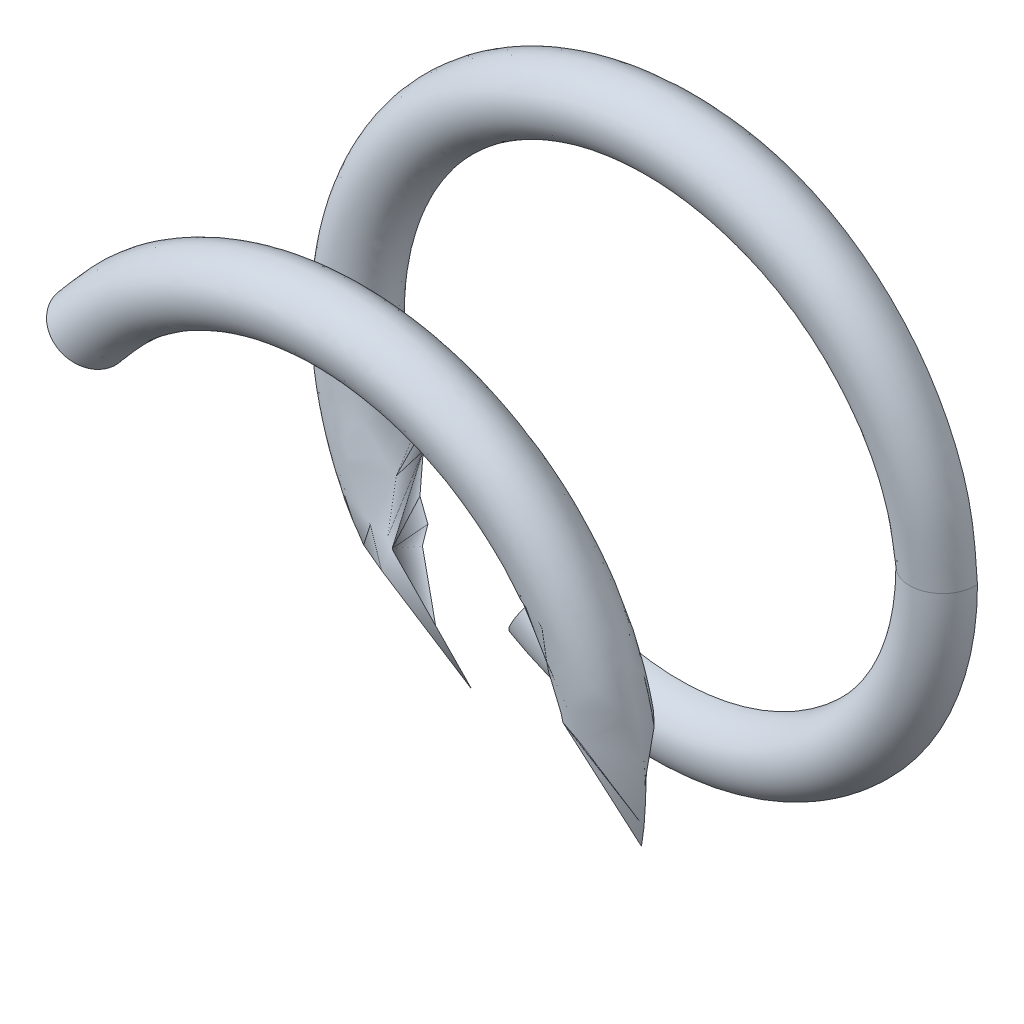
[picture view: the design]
ISO-10303-21;
HEADER;
FILE_DESCRIPTION(('STEP AP214'),'2;1');
FILE_NAME('part.step','',(''),(''),'','','');
FILE_SCHEMA(('AUTOMOTIVE_DESIGN { 1 0 10303 214 1 1 1 1 }'));
ENDSEC;
DATA;
#1=APPLICATION_CONTEXT('core data for automotive mechanical design processes');
#2=APPLICATION_PROTOCOL_DEFINITION('international standard','automotive_design',2000,#1);
#3=PRODUCT_CONTEXT('',#1,'mechanical');
#4=PRODUCT('Part','Part','',(#3));
#5=PRODUCT_RELATED_PRODUCT_CATEGORY('part','',(#4));
#6=PRODUCT_DEFINITION_FORMATION('','',#4);
#7=PRODUCT_DEFINITION_CONTEXT('part definition',#1,'design');
#8=PRODUCT_DEFINITION('design','',#6,#7);
#9=PRODUCT_DEFINITION_SHAPE('','',#8);
#10=(LENGTH_UNIT() NAMED_UNIT(*) SI_UNIT(.MILLI.,.METRE.));
#11=(NAMED_UNIT(*) PLANE_ANGLE_UNIT() SI_UNIT($,.RADIAN.));
#12=(NAMED_UNIT(*) SI_UNIT($,.STERADIAN.) SOLID_ANGLE_UNIT());
#13=UNCERTAINTY_MEASURE_WITH_UNIT(LENGTH_MEASURE(1.E-05),#10,'distance_accuracy_value','');
#14=(GEOMETRIC_REPRESENTATION_CONTEXT(3) GLOBAL_UNCERTAINTY_ASSIGNED_CONTEXT((#13)) GLOBAL_UNIT_ASSIGNED_CONTEXT((#10,
#11,#12)) REPRESENTATION_CONTEXT('',''));
#15=CARTESIAN_POINT('',(0.,0.,0.));
#16=DIRECTION('',(0.,0.,1.));
#17=DIRECTION('',(1.,0.,0.));
#18=AXIS2_PLACEMENT_3D('',#15,#16,#17);
#19=CARTESIAN_POINT('',(12.,0.,1.5));
#20=CARTESIAN_POINT('',(11.9418927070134,0.888508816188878,1.55892430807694));
#21=CARTESIAN_POINT('',(11.8254807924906,2.66854376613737,1.67697302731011));
#22=CARTESIAN_POINT('',(10.9146193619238,5.20828516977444,1.85413695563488));
#23=CARTESIAN_POINT('',(9.50351753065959,7.49108137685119,2.0312750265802));
#24=CARTESIAN_POINT('',(7.612969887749,9.4020238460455,2.20834408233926));
#25=CARTESIAN_POINT('',(5.35173785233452,10.8517466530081,2.3853875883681));
#26=CARTESIAN_POINT('',(2.8241644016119,11.7636999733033,2.56252409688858));
#27=CARTESIAN_POINT('',(0.158422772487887,12.0990888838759,2.73957486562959));
#28=CARTESIAN_POINT('',(-2.51533122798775,11.8334460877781,2.91666327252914));
#29=CARTESIAN_POINT('',(-5.0656074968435,10.9883084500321,3.09375974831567));
#30=CARTESIAN_POINT('',(-7.36509357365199,9.59829820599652,3.27081824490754));
#31=CARTESIAN_POINT('',(-9.30210830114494,7.73654640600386,3.44793628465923));
#32=CARTESIAN_POINT('',(-10.7805494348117,5.49293821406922,3.62497834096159));
#33=CARTESIAN_POINT('',(-11.7258602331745,2.97799692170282,3.8021033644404));
#34=CARTESIAN_POINT('',(-12.0958270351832,0.31675811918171,3.97915157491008));
#35=CARTESIAN_POINT('',(-11.8653071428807,-2.3601936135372,4.15625805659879));
#36=CARTESIAN_POINT('',(-11.0539405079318,-4.92146957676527,4.33333370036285));
#37=CARTESIAN_POINT('',(-9.69359276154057,-7.2386166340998,4.51040787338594));
#38=CARTESIAN_POINT('',(-7.85793807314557,-9.20036793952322,4.68751556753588));
#39=CARTESIAN_POINT('',(-5.63336414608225,-10.7073455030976,4.86456316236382));
#40=CARTESIAN_POINT('',(-3.13134399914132,-11.6862177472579,5.04168825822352));
#41=CARTESIAN_POINT('',(-0.475027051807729,-12.0903507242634,5.21873018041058));
#42=CARTESIAN_POINT('',(2.2046758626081,-11.8952806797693,5.39584853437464));
#43=CARTESIAN_POINT('',(4.77640624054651,-11.1174868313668,5.57290865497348));
#44=CARTESIAN_POINT('',(7.11097475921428,-9.7873304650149,5.74999960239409));
#45=CARTESIAN_POINT('',(9.09701650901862,-7.97795538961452,5.92709199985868));
#46=CARTESIAN_POINT('',(10.6323245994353,-5.77282598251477,6.10415094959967));
#47=CARTESIAN_POINT('',(11.6446337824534,-3.28417762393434,6.28127007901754));
#48=CARTESIAN_POINT('',(12.0827018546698,-0.633204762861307,6.45831173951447));
#49=CARTESIAN_POINT('',(11.9233675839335,2.04880154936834,6.63543656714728));
#50=CARTESIAN_POINT('',(11.1789246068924,4.63044315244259,6.81248492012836));
#51=CARTESIAN_POINT('',(9.87952006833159,6.98219921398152,6.98959141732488));
#52=CARTESIAN_POINT('',(8.09653525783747,8.9920289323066,7.16666702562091));
#53=CARTESIAN_POINT('',(5.91132700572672,10.5555447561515,7.34374120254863));
#54=CARTESIAN_POINT('',(3.43645684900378,11.6010656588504,7.52084890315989));
#55=CARTESIAN_POINT('',(0.791264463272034,12.0729424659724,7.69789649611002));
#56=CARTESIAN_POINT('',(-1.89258789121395,11.9495234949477,7.87502159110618));
#57=CARTESIAN_POINT('',(-4.48362986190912,11.2382958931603,8.05206351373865));
#58=CARTESIAN_POINT('',(-6.85231815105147,9.97015717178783,8.22918186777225));
#59=CARTESIAN_POINT('',(-8.88535349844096,8.21359015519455,8.40624198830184));
#60=CARTESIAN_POINT('',(-10.4770646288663,6.04887728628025,8.58333293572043));
#61=CARTESIAN_POINT('',(-11.5554649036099,3.5881349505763,8.76042533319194));
#62=CARTESIAN_POINT('',(-12.0611317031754,0.949182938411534,8.93748428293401));
#63=CARTESIAN_POINT('',(-11.9736976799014,-1.73605370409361,9.11460341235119));
#64=CARTESIAN_POINT('',(-11.2956449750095,-4.33601625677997,9.29164507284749));
#65=CARTESIAN_POINT('',(-10.0592156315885,-6.72134385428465,9.46876990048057));
#66=CARTESIAN_POINT('',(-8.32908489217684,-8.77699857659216,9.64581825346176));
#67=CARTESIAN_POINT('',(-6.18547441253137,-10.3969192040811,9.8229247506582));
#68=CARTESIAN_POINT('',(-3.7391653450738,-11.5077847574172,10.0000003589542));
#69=CARTESIAN_POINT('',(-1.10693909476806,-12.0473232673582,10.177074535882));
#70=CARTESIAN_POINT('',(1.57921895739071,-11.9958337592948,10.3541822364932));
#71=CARTESIAN_POINT('',(4.18765203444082,-11.3510180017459,10.5312298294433));
#72=CARTESIAN_POINT('',(6.5892741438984,-10.1466480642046,10.7083549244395));
#73=CARTESIAN_POINT('',(8.66702643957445,-8.44303760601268,10.885396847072));
#74=CARTESIAN_POINT('',(10.3151323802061,-6.3211029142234,11.0625152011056));
#75=CARTESIAN_POINT('',(11.4579424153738,-3.88948912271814,11.2395753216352));
#76=CARTESIAN_POINT('',(12.0315748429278,-1.26451827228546,11.4166662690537));
#77=CARTESIAN_POINT('',(12.0158684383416,1.42210661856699,11.5937586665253));
#78=CARTESIAN_POINT('',(11.4044595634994,4.03858245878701,11.7708176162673));
#79=CARTESIAN_POINT('',(10.2324004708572,6.45610557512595,11.9479367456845));
#80=CARTESIAN_POINT('',(8.55546846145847,8.55550067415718,12.1249784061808));
#81=CARTESIAN_POINT('',(6.45573391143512,10.2317047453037,12.3021032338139));
#82=CARTESIAN_POINT('',(4.03907073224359,11.4059312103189,12.4791515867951));
#83=CARTESIAN_POINT('',(1.42190403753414,12.0139174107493,12.6562580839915));
#84=CARTESIAN_POINT('',(-1.26474022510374,12.0337400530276,12.8333336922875));
#85=CARTESIAN_POINT('',(-3.88884864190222,11.4560101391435,13.0104078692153));
#86=CARTESIAN_POINT('',(-6.32183345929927,10.3164132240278,13.1875155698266));
#87=CARTESIAN_POINT('',(-8.44248545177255,8.66639940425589,13.3645631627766));
#88=CARTESIAN_POINT('',(-10.1466150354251,6.58932500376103,13.5416882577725));
#89=CARTESIAN_POINT('',(-11.3518154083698,4.18790141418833,13.7187301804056));
#90=CARTESIAN_POINT('',(-11.9943665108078,1.57907253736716,13.8958485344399));
#91=CARTESIAN_POINT('',(-12.0493489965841,-1.10713991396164,14.0729086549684));
#92=CARTESIAN_POINT('',(-11.5057164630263,-3.73848743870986,14.24999960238));
#93=CARTESIAN_POINT('',(-10.3986191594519,-6.18645303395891,14.4270919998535));
#94=CARTESIAN_POINT('',(-8.77585275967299,-8.32804026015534,14.6041509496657));
#95=CARTESIAN_POINT('',(-6.72182826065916,-10.0598381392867,14.7812700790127));
#96=CARTESIAN_POINT('',(-4.33597372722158,-11.2956612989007,14.9583117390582));
#97=CARTESIAN_POINT('',(-1.73599715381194,-11.9729109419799,15.1354365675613));
#98=CARTESIAN_POINT('',(0.949335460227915,-12.0626747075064,15.3124849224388));
#99=CARTESIAN_POINT('',(3.58752645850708,-11.5536001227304,15.4895914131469));
#100=CARTESIAN_POINT('',(6.04996074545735,-10.4789525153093,15.6666670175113));
#101=CARTESIAN_POINT('',(8.21221908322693,-8.88384871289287,15.8437412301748));
#102=CARTESIAN_POINT('',(9.9713452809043,-6.85319072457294,16.0208489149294));
#103=CARTESIAN_POINT('',(11.2375374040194,-4.48328224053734,16.1978963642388));
#104=CARTESIAN_POINT('',(11.9495143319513,-1.89264831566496,16.3750216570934));
#105=CARTESIAN_POINT('',(12.0737655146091,0.791361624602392,16.5520639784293));
#106=CARTESIAN_POINT('',(11.5996708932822,3.43599518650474,16.7291812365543));
#107=CARTESIAN_POINT('',(10.5573384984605,5.91234692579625,16.9062409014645));
#108=CARTESIAN_POINT('',(8.99037772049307,8.09504304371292,17.0833359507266));
#109=CARTESIAN_POINT('',(6.98332136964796,9.88105914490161,17.2604257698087));
#110=CARTESIAN_POINT('',(4.62994918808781,11.1777062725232,17.4374753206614));
#111=CARTESIAN_POINT('',(2.04876537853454,11.9241713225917,17.6146127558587));
#112=CARTESIAN_POINT('',(-0.632669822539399,12.0816416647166,17.7916559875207));
#113=CARTESIAN_POINT('',(-3.28525807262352,11.6459653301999,17.9687245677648));
#114=CARTESIAN_POINT('',(-5.76915230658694,10.6299279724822,18.1458636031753));
#115=CARTESIAN_POINT('',(-7.99811145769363,9.10921097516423,18.3230262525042));
#116=CARTESIAN_POINT('',(-9.13869069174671,7.73781643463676,18.4410755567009));
#117=CARTESIAN_POINT('',(-9.70801192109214,7.0532835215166,18.4999999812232));
#118=CARTESIAN_POINT('',(15.,0.,1.5));
#119=CARTESIAN_POINT('',(14.9276553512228,1.11042856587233,1.55878513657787));
#120=CARTESIAN_POINT('',(14.7827203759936,3.33505664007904,1.67655504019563));
#121=CARTESIAN_POINT('',(13.6429238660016,6.5105284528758,1.85534896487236));
#122=CARTESIAN_POINT('',(11.8807197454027,9.3626606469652,2.03101922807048));
#123=CARTESIAN_POINT('',(9.51290570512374,11.7553577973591,2.20904237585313));
#124=CARTESIAN_POINT('',(6.69387271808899,13.5624791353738,2.38486552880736));
#125=CARTESIAN_POINT('',(3.52747304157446,14.7059321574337,2.56347098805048));
#126=CARTESIAN_POINT('',(0.199783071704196,15.1233519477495,2.73935694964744));
#127=CARTESIAN_POINT('',(-3.14423055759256,14.7925656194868,2.91687073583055));
#128=CARTESIAN_POINT('',(-6.33358695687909,13.7342622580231,3.09441074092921));
#129=CARTESIAN_POINT('',(-9.20437195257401,11.9999969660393,3.27049082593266));
#130=CARTESIAN_POINT('',(-11.6301986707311,9.66762446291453,3.44895475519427));
#131=CARTESIAN_POINT('',(-13.4738219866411,6.869902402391,3.62439605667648));
#132=CARTESIAN_POINT('',(-14.6586718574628,3.71898281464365,3.80308516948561));
#133=CARTESIAN_POINT('',(-15.1193433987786,0.399199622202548,3.97874576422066));
#134=CARTESIAN_POINT('',(-14.8320557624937,-2.95186917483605,4.15679993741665));
#135=CARTESIAN_POINT('',(-13.8170019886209,-6.15164800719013,4.33357133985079));
#136=CARTESIAN_POINT('',(-12.1184562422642,-9.04740467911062,4.51034039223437));
#137=CARTESIAN_POINT('',(-9.81982226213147,-11.502423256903,4.6883952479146));
#138=CARTESIAN_POINT('',(-7.0451667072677,-13.3826505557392,4.86405793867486));
#139=CARTESIAN_POINT('',(-3.91024372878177,-14.609069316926,5.04274627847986));
#140=CARTESIAN_POINT('',(-0.597783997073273,-15.1126021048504,5.2181775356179));
#141=CARTESIAN_POINT('',(2.75875004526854,-14.8691846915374,5.3966524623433));
#142=CARTESIAN_POINT('',(5.96855784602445,-13.897194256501,5.57276744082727));
#143=CARTESIAN_POINT('',(8.88913913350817,-12.2347932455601,5.75023694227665));
#144=CARTESIAN_POINT('',(11.3722609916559,-9.97075780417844,5.92770789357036));
#145=CARTESIAN_POINT('',(13.2894409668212,-7.21879822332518,6.10382170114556));
#146=CARTESIAN_POINT('',(14.5568913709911,-4.10138542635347,6.28229740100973));
#147=CARTESIAN_POINT('',(15.1031904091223,-0.795669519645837,6.45772840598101));
#148=CARTESIAN_POINT('',(14.9040104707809,2.56475868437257,6.63641647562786));
#149=CARTESIAN_POINT('',(13.9745762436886,5.78490406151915,6.81207987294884));
#150=CARTESIAN_POINT('',(12.3491236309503,8.72940711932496,6.99013357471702));
#151=CARTESIAN_POINT('',(10.120358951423,11.2396911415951,7.16690436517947));
#152=CARTESIAN_POINT('',(7.39084961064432,13.1942357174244,7.34367372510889));
#153=CARTESIAN_POINT('',(4.29239696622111,14.5020680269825,7.5217286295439));
#154=CARTESIAN_POINT('',(0.992865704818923,15.0911870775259,7.69739126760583));
#155=CARTESIAN_POINT('',(-2.36985841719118,14.936488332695,7.87607960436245));
#156=CARTESIAN_POINT('',(-5.60074619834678,14.0491896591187,8.05151087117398));
#157=CARTESIAN_POINT('',(-8.56808583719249,12.4615914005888,8.2299857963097));
#158=CARTESIAN_POINT('',(-11.1050470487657,10.2680875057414,8.40610077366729));
#159=CARTESIAN_POINT('',(-13.0969714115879,7.56150118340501,8.5835702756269));
#160=CARTESIAN_POINT('',(-14.4445499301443,4.48322524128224,8.7610412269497));
#161=CARTESIAN_POINT('',(-15.0766581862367,1.18939771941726,8.9371550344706));
#162=CARTESIAN_POINT('',(-14.9665657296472,-2.17401910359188,9.11563073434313));
#163=CARTESIAN_POINT('',(-14.1210789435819,-5.41614069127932,9.29106173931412));
#164=CARTESIAN_POINT('',(-12.5723097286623,-8.40503083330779,9.46974980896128));
#165=CARTESIAN_POINT('',(-10.4134781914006,-10.9687450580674,9.64541320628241));
#166=CARTESIAN_POINT('',(-7.73091605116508,-12.9975513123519,9.82346690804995));
#167=CARTESIAN_POINT('',(-4.67381370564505,-14.3842896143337,10.0002376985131));
#168=CARTESIAN_POINT('',(-1.3852979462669,-15.0596634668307,10.1770070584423));
#169=CARTESIAN_POINT('',(1.97722271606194,-14.9941735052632,10.3550619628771));
#170=CARTESIAN_POINT('',(5.23111081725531,-14.1903202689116,10.5307246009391));
#171=CARTESIAN_POINT('',(8.24019051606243,-12.6812528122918,10.7094129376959));
#172=CARTESIAN_POINT('',(10.8308564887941,-10.556544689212,10.8848442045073));
#173=CARTESIAN_POINT('',(12.8959217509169,-7.89927574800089,11.0633191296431));
#174=CARTESIAN_POINT('',(14.3213727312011,-4.86353514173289,11.2394341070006));
#175=CARTESIAN_POINT('',(15.0402183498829,-1.58075687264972,11.4169036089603));
#176=CARTESIAN_POINT('',(15.0192449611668,1.77949769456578,11.594374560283));
#177=CARTESIAN_POINT('',(14.2569842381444,5.04566045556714,11.7704883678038));
#178=CARTESIAN_POINT('',(12.7883849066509,8.0735159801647,11.9489640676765));
#179=CARTESIAN_POINT('',(10.6973046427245,10.6914509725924,12.1243950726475));
#180=CARTESIAN_POINT('',(8.06674241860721,12.7919967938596,12.3030831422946));
#181=CARTESIAN_POINT('',(5.0517951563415,14.2559903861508,12.4787465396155));
#182=CARTESIAN_POINT('',(1.77596285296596,15.0183008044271,12.6568002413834));
#183=CARTESIAN_POINT('',(-1.58087639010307,15.0417137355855,12.8335710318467));
#184=CARTESIAN_POINT('',(-4.85978431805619,14.3211385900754,13.0103403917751));
#185=CARTESIAN_POINT('',(-7.90496262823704,12.893650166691,13.1883952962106));
#186=CARTESIAN_POINT('',(-10.5505807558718,10.8358181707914,13.3640579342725));
#187=CARTESIAN_POINT('',(-12.6857188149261,8.233313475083,13.542746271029));
#188=CARTESIAN_POINT('',(-14.1882132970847,5.23857723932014,13.7181775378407));
#189=CARTESIAN_POINT('',(-14.9939356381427,1.9711035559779,13.896652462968));
#190=CARTESIAN_POINT('',(-15.0614029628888,-1.38196663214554,14.0727674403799));
#191=CARTESIAN_POINT('',(-14.3828748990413,-4.67331466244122,14.2502369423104));
#192=CARTESIAN_POINT('',(-12.9969760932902,-7.73452931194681,14.4277078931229));
#193=CARTESIAN_POINT('',(-10.9721481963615,-10.4082780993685,14.6038217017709));
#194=CARTESIAN_POINT('',(-8.39897614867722,-12.5770286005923,14.7822974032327));
#195=CARTESIAN_POINT('',(-5.42386918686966,-14.1181122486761,14.9577283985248));
#196=CARTESIAN_POINT('',(-2.16636208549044,-14.9671103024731,15.1364164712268));
#197=CARTESIAN_POINT('',(1.18338918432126,-15.0782454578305,15.3120799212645));
#198=CARTESIAN_POINT('',(4.48607049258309,-14.4422496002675,15.4901335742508));
#199=CARTESIAN_POINT('',(7.56221853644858,-13.0982890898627,15.6669040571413));
#200=CARTESIAN_POINT('',(10.2645657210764,-11.1063586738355,15.8436740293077));
#201=CARTESIAN_POINT('',(12.4658624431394,-8.56369710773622,16.0217294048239));
#202=CARTESIAN_POINT('',(14.0457602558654,-5.60770580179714,16.1973892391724));
#203=CARTESIAN_POINT('',(14.9377719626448,-2.36175805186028,16.3760786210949));
#204=CARTESIAN_POINT('',(15.0922913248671,0.985188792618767,16.5515201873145));
#205=CARTESIAN_POINT('',(14.4993710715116,4.29787737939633,16.7299833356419));
#206=CARTESIAN_POINT('',(13.1972008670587,7.38854503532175,16.9060645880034));
#207=CARTESIAN_POINT('',(11.2385179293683,10.1193375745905,17.0836031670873));
#208=CARTESIAN_POINT('',(8.72750137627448,12.3520334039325,17.2611183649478));
#209=CARTESIAN_POINT('',(5.79039247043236,13.9714035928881,17.4370031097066));
#210=CARTESIAN_POINT('',(2.55631396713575,14.9060820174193,17.6156094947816));
#211=CARTESIAN_POINT('',(-0.786463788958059,15.1022845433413,17.7914323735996));
#212=CARTESIAN_POINT('',(-4.1083363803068,14.5573982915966,17.9694550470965));
#213=CARTESIAN_POINT('',(-7.21093180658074,13.2871361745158,18.1451262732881));
#214=CARTESIAN_POINT('',(-9.99877614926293,11.3866756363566,18.3239189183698));
#215=CARTESIAN_POINT('',(-11.4237615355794,9.67236469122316,18.4416894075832));
#216=CARTESIAN_POINT('',(-12.1350443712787,8.81666472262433,18.5004746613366));
#217=CARTESIAN_POINT('',(15.,0.,-1.5));
#218=CARTESIAN_POINT('',(14.9275300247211,1.11037306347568,-1.44121487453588));
#219=CARTESIAN_POINT('',(14.782343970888,3.3348899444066,-1.32344499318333));
#220=CARTESIAN_POINT('',(13.6439737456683,6.51112453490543,-1.14465089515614));
#221=CARTESIAN_POINT('',(11.880549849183,9.36247980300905,-0.968980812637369));
#222=CARTESIAN_POINT('',(9.51333714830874,11.7559009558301,-0.790957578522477));
#223=CARTESIAN_POINT('',(6.69360174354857,13.5620400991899,-0.615134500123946));
#224=CARTESIAN_POINT('',(3.52775582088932,14.7068335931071,-0.436528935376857));
#225=CARTESIAN_POINT('',(0.199669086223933,15.1231403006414,-0.260643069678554));
#226=CARTESIAN_POINT('',(-3.14415932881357,14.7927948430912,-0.0831292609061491));
#227=CARTESIAN_POINT('',(-6.33396481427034,13.7348041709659,0.0944107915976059));
#228=CARTESIAN_POINT('',(-9.20412122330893,11.999786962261,0.270490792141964));
#229=CARTESIAN_POINT('',(-11.6310085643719,9.66823422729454,0.448954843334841));
#230=CARTESIAN_POINT('',(-13.4733161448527,6.86963617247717,0.624396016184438));
#231=CARTESIAN_POINT('',(-14.6596092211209,3.71925552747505,0.803085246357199));
#232=CARTESIAN_POINT('',(-15.1189474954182,0.399102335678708,0.978745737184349));
#233=CARTESIAN_POINT('',(-14.8326056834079,-2.95187546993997,1.15679996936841));
#234=CARTESIAN_POINT('',(-13.8171704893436,-6.1518585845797,1.33357135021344));
#235=CARTESIAN_POINT('',(-12.1184670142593,-9.04728629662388,1.51034037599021));
#236=CARTESIAN_POINT('',(-9.82032474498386,-11.5031462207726,1.6883953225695));
#237=CARTESIAN_POINT('',(-7.04496655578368,-13.3821963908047,1.86405789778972));
#238=CARTESIAN_POINT('',(-3.91050789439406,-14.6100868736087,2.04274636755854));
#239=CARTESIAN_POINT('',(-0.597713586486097,-15.1120615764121,2.21817750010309));
#240=CARTESIAN_POINT('',(2.75882553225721,-14.8699840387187,2.39665251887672));
#241=CARTESIAN_POINT('',(5.96860870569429,-13.8970237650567,2.57276742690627));
#242=CARTESIAN_POINT('',(8.88918793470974,-12.2350536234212,2.75023694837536));
#243=CARTESIAN_POINT('',(11.3727988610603,-9.97107743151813,2.92770793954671));
#244=CARTESIAN_POINT('',(13.2891244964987,-7.21870820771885,3.10382166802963));
#245=CARTESIAN_POINT('',(14.5578879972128,-4.1016147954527,3.28229749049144));
#246=CARTESIAN_POINT('',(15.1026189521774,-0.795632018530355,3.45772836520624));
#247=CARTESIAN_POINT('',(14.9049758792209,2.56489033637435,3.63641655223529));
#248=CARTESIAN_POINT('',(13.9741756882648,5.78483223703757,3.81207984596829));
#249=CARTESIAN_POINT('',(12.3496236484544,8.72963673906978,3.99013360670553));
#250=CARTESIAN_POINT('',(10.1204270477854,11.2399518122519,4.16690437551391));
#251=CARTESIAN_POINT('',(7.3909076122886,13.1941319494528,4.34367370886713));
#252=CARTESIAN_POINT('',(4.29256195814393,14.5029329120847,4.5217287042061));
#253=CARTESIAN_POINT('',(0.992867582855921,15.090690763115,4.69739122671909));
#254=CARTESIAN_POINT('',(-2.37003096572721,14.9375253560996,4.87607969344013));
#255=CARTESIAN_POINT('',(-5.60059066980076,14.0486672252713,5.05151083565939));
#256=CARTESIAN_POINT('',(-8.56847992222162,12.4622909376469,5.22998585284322));
#257=CARTESIAN_POINT('',(-11.1050241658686,10.267911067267,5.40610075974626));
#258=CARTESIAN_POINT('',(-13.0971218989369,7.56171920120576,5.58357028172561));
#259=CARTESIAN_POINT('',(-14.4451713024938,4.48329846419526,5.76104127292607));
#260=CARTESIAN_POINT('',(-15.0763324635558,1.18944420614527,5.93715500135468));
#261=CARTESIAN_POINT('',(-14.9675694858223,-2.17421492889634,6.11563082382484));
#262=CARTESIAN_POINT('',(-14.1205416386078,-5.41594251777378,6.29106169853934));
#263=CARTESIAN_POINT('',(-12.5731381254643,-8.4055437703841,6.46974988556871));
#264=CARTESIAN_POINT('',(-10.4131414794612,-10.9685165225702,6.64541317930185));
#265=CARTESIAN_POINT('',(-7.73127944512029,-12.9979644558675,6.82346694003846));
#266=CARTESIAN_POINT('',(-4.67376989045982,-14.3845554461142,7.00023770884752));
#267=CARTESIAN_POINT('',(-1.38539313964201,-15.0595922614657,7.17700704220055));
#268=CARTESIAN_POINT('',(1.97742376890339,-14.9950307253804,7.35506203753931));
#269=CARTESIAN_POINT('',(5.23090723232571,-14.1898676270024,7.53072456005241));
#270=CARTESIAN_POINT('',(8.24076994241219,-12.6821299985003,7.70941302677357));
#271=CARTESIAN_POINT('',(10.8305019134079,-10.5561306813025,7.88484416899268));
#272=CARTESIAN_POINT('',(12.8965662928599,-7.89975451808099,8.06331918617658));
#273=CARTESIAN_POINT('',(14.3212800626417,-4.86338326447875,8.23943409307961));
#274=CARTESIAN_POINT('',(15.0404445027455,-1.58089483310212,8.41690361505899));
#275=CARTESIAN_POINT('',(15.0198423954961,1.77968353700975,8.5943746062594));
#276=CARTESIAN_POINT('',(14.2567055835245,5.04548550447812,8.7704883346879));
#277=CARTESIAN_POINT('',(12.7892222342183,8.07410313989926,8.94896415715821));
#278=CARTESIAN_POINT('',(10.6968943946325,10.6910513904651,9.12439503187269));
#279=CARTESIAN_POINT('',(8.06729056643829,12.7928023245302,9.30308321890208));
#280=CARTESIAN_POINT('',(5.05158050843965,14.2556446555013,9.47874651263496));
#281=CARTESIAN_POINT('',(1.77612678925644,15.0188260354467,9.65680027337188));
#282=CARTESIAN_POINT('',(-1.58102454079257,15.0419387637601,9.83357104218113));
#283=CARTESIAN_POINT('',(-4.8596683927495,14.3211122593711,10.0103403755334));
#284=CARTESIAN_POINT('',(-7.90549496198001,12.8943515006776,10.1883953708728));
#285=CARTESIAN_POINT('',(-10.5502106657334,10.8354874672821,10.3640578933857));
#286=CARTESIAN_POINT('',(-12.6866049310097,8.23387915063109,10.5427463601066));
#287=CARTESIAN_POINT('',(-14.1877209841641,5.23834324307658,10.7181775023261));
#288=CARTESIAN_POINT('',(-14.9947191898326,1.97127877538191,10.8966525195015));
#289=CARTESIAN_POINT('',(-15.0612565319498,-1.38206768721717,11.0727674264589));
#290=CARTESIAN_POINT('',(-14.3831376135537,-4.67328061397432,11.2502369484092));
#291=CARTESIAN_POINT('',(-12.9974462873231,-7.73494208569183,11.4277079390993));
#292=CARTESIAN_POINT('',(-10.971964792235,-10.4080049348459,11.603821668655));
#293=CARTESIAN_POINT('',(-8.3995022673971,-12.577905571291,11.7822974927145));
#294=CARTESIAN_POINT('',(-5.42365692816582,-14.1175803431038,11.9577283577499));
#295=CARTESIAN_POINT('',(-2.1665352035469,-14.9680691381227,12.1364165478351));
#296=CARTESIAN_POINT('',(1.18344465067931,-15.0778423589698,12.3120798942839));
#297=CARTESIAN_POINT('',(4.48613437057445,-14.4427961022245,12.4901336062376));
#298=CARTESIAN_POINT('',(7.56244527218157,-13.0984341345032,12.6669040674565));
#299=CARTESIAN_POINT('',(10.264449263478,-11.106382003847,12.843674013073));
#300=CARTESIAN_POINT('',(12.4666346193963,-8.5641217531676,13.0217294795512));
#301=CARTESIAN_POINT('',(14.0452859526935,-5.60755337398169,13.1973891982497));
#302=CARTESIAN_POINT('',(14.9388105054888,-2.36191421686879,13.3760787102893));
#303=CARTESIAN_POINT('',(15.0917553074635,0.985202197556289,13.5515201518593));
#304=CARTESIAN_POINT('',(14.500156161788,4.29803627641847,13.7299833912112));
#305=CARTESIAN_POINT('',(13.1969943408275,7.38856229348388,13.9060645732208));
#306=CARTESIAN_POINT('',(11.2387965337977,10.1194305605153,14.0836031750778));
#307=CARTESIAN_POINT('',(8.7278095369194,12.352662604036,14.2611184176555));
#308=CARTESIAN_POINT('',(5.79027500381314,13.9709501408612,14.4370030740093));
#309=CARTESIAN_POINT('',(2.5564331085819,14.9070682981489,14.6156095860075));
#310=CARTESIAN_POINT('',(-0.786458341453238,15.1020694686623,14.7914323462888));
#311=CARTESIAN_POINT('',(-4.10849776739,14.5581051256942,14.9694550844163));
#312=CARTESIAN_POINT('',(-7.21066093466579,13.2864572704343,15.1451262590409));
#313=CARTESIAN_POINT('',(-9.9992992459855,11.3873920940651,15.3239189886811));
#314=CARTESIAN_POINT('',(-11.4241918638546,9.67278935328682,15.4416894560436));
#315=CARTESIAN_POINT('',(-12.1354283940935,8.81694373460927,15.5004746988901));
#316=CARTESIAN_POINT('',(12.,0.,-1.5));
#317=CARTESIAN_POINT('',(11.9417673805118,0.888453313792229,-1.44107570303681));
#318=CARTESIAN_POINT('',(11.825104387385,2.66837707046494,-1.32302700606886));
#319=CARTESIAN_POINT('',(10.9156692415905,5.20888125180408,-1.14586290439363));
#320=CARTESIAN_POINT('',(9.50334763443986,7.49090053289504,-0.968725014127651));
#321=CARTESIAN_POINT('',(7.613401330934,9.40256700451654,-0.791655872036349));
#322=CARTESIAN_POINT('',(5.3514668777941,10.8513076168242,-0.614612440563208));
#323=CARTESIAN_POINT('',(2.82444718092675,11.7646014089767,-0.437475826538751));
#324=CARTESIAN_POINT('',(0.158308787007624,12.0988772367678,-0.260425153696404));
#325=CARTESIAN_POINT('',(-2.51525999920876,11.8336753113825,-0.0833367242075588));
#326=CARTESIAN_POINT('',(-5.06598535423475,10.9888503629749,0.0937597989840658));
#327=CARTESIAN_POINT('',(-7.36484284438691,9.59808820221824,0.270818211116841));
#328=CARTESIAN_POINT('',(-9.30291819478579,7.73715617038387,0.4479363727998));
#329=CARTESIAN_POINT('',(-10.7800435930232,5.4926719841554,0.624978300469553));
#330=CARTESIAN_POINT('',(-11.7267975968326,2.97826963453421,0.802103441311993));
#331=CARTESIAN_POINT('',(-12.0954311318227,0.316660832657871,0.97915154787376));
#332=CARTESIAN_POINT('',(-11.8658570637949,-2.36019990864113,1.15625808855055));
#333=CARTESIAN_POINT('',(-11.0541090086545,-4.92168015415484,1.3333337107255));
#334=CARTESIAN_POINT('',(-9.69360353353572,-7.23849825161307,1.51040785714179));
#335=CARTESIAN_POINT('',(-7.85844055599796,-9.20109090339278,1.68751564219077));
#336=CARTESIAN_POINT('',(-5.63316399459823,-10.7068913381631,1.86456312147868));
#337=CARTESIAN_POINT('',(-3.13160816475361,-11.6872353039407,2.0416883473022));
#338=CARTESIAN_POINT('',(-0.474956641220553,-12.0898101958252,2.21873014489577));
#339=CARTESIAN_POINT('',(2.20475134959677,-11.8960800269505,2.39584859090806));
#340=CARTESIAN_POINT('',(4.77645710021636,-11.1173163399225,2.57290864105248));
#341=CARTESIAN_POINT('',(7.11102356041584,-9.787590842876,2.74999960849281));
#342=CARTESIAN_POINT('',(9.09755437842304,-7.97827501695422,2.92709204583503));
#343=CARTESIAN_POINT('',(10.6320081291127,-5.77273596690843,3.10415091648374));
#344=CARTESIAN_POINT('',(11.6456304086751,-3.28440699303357,3.28127016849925));
#345=CARTESIAN_POINT('',(12.0821303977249,-0.633167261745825,3.45831169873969));
#346=CARTESIAN_POINT('',(11.9243329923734,2.04893320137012,3.63543664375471));
#347=CARTESIAN_POINT('',(11.1785240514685,4.63037132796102,3.8124848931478));
#348=CARTESIAN_POINT('',(9.88002008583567,6.98242883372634,3.98959144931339));
#349=CARTESIAN_POINT('',(8.09660335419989,8.99228960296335,4.16666703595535));
#350=CARTESIAN_POINT('',(5.911385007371,10.5554409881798,4.34374118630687));
#351=CARTESIAN_POINT('',(3.4366218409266,11.6019305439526,4.5208489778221));
#352=CARTESIAN_POINT('',(0.791266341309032,12.0724461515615,4.69789645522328));
#353=CARTESIAN_POINT('',(-1.89276043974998,11.9505605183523,4.87502168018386));
#354=CARTESIAN_POINT('',(-4.4834743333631,11.2377734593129,5.05206347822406));
#355=CARTESIAN_POINT('',(-6.85271223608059,9.97085670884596,5.22918192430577));
#356=CARTESIAN_POINT('',(-8.88533061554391,8.21341371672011,5.4062419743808));
#357=CARTESIAN_POINT('',(-10.4772151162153,6.049095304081,5.58333294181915));
#358=CARTESIAN_POINT('',(-11.5560862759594,3.58820817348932,5.7604253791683));
#359=CARTESIAN_POINT('',(-12.0608059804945,0.949229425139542,5.93748424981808));
#360=CARTESIAN_POINT('',(-11.9747014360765,-1.73624952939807,6.1146035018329));
#361=CARTESIAN_POINT('',(-11.2951076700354,-4.33581808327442,6.29164503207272));
#362=CARTESIAN_POINT('',(-10.0600440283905,-6.72185679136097,6.468769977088));
#363=CARTESIAN_POINT('',(-8.32874818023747,-8.7767700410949,6.64581822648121));
#364=CARTESIAN_POINT('',(-6.18583780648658,-10.3973323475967,6.82292478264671));
#365=CARTESIAN_POINT('',(-3.73912152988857,-11.5080505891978,7.00000036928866));
#366=CARTESIAN_POINT('',(-1.10703428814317,-12.0472520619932,7.17707451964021));
#367=CARTESIAN_POINT('',(1.57942001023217,-11.996690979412,7.35418231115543));
#368=CARTESIAN_POINT('',(4.18744844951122,-11.3505653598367,7.53122978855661));
#369=CARTESIAN_POINT('',(6.58985357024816,-10.1475252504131,7.70835501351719));
#370=CARTESIAN_POINT('',(8.66667186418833,-8.44262359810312,7.88539681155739));
#371=CARTESIAN_POINT('',(10.3157769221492,-6.32158168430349,8.06251525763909));
#372=CARTESIAN_POINT('',(11.4578497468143,-3.88933724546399,8.23957530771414));
#373=CARTESIAN_POINT('',(12.0318009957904,-1.26465623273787,8.41666627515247));
#374=CARTESIAN_POINT('',(12.0164658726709,1.42229246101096,8.59375871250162));
#375=CARTESIAN_POINT('',(11.4041809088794,4.03840750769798,8.77081758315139));
#376=CARTESIAN_POINT('',(10.2332377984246,6.4566927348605,8.94793683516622));
#377=CARTESIAN_POINT('',(8.55505821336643,8.55510109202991,9.12497836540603));
#378=CARTESIAN_POINT('',(6.45628205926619,10.2325102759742,9.3021033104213));
#379=CARTESIAN_POINT('',(4.03885608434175,11.4055854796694,9.47915155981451));
#380=CARTESIAN_POINT('',(1.42206797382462,12.0144426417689,9.65625811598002));
#381=CARTESIAN_POINT('',(-1.26488837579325,12.0339650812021,9.83333370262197));
#382=CARTESIAN_POINT('',(-3.88873271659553,11.4559838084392,10.0104078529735));
#383=CARTESIAN_POINT('',(-6.32236579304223,10.3171145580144,10.1875156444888));
#384=CARTESIAN_POINT('',(-8.44211536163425,8.66606870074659,10.3645631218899));
#385=CARTESIAN_POINT('',(-10.1475011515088,6.58989067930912,10.5416883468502));
#386=CARTESIAN_POINT('',(-11.3513230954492,4.18766741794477,10.718730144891));
#387=CARTESIAN_POINT('',(-11.9951500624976,1.57924775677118,10.8958485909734));
#388=CARTESIAN_POINT('',(-12.0492025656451,-1.10724096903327,11.0729086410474));
#389=CARTESIAN_POINT('',(-11.5059791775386,-3.73845339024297,11.2499996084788));
#390=CARTESIAN_POINT('',(-10.3990893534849,-6.18686580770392,11.4270920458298));
#391=CARTESIAN_POINT('',(-8.77566935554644,-8.32776709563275,11.6041509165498));
#392=CARTESIAN_POINT('',(-6.72235437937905,-10.0607151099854,11.7812701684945));
#393=CARTESIAN_POINT('',(-4.33576146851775,-11.2951293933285,11.9583116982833));
#394=CARTESIAN_POINT('',(-1.7361702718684,-11.9738697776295,12.1354366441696));
#395=CARTESIAN_POINT('',(0.949390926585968,-12.0622716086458,12.3124848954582));
#396=CARTESIAN_POINT('',(3.58759033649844,-11.5541466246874,12.4895914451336));
#397=CARTESIAN_POINT('',(6.05018748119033,-10.4790975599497,12.6666670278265));
#398=CARTESIAN_POINT('',(8.21210262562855,-8.88387204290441,12.84374121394));
#399=CARTESIAN_POINT('',(9.97211745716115,-6.85361537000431,13.0208489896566));
#400=CARTESIAN_POINT('',(11.2370631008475,-4.48312981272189,13.1978963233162));
#401=CARTESIAN_POINT('',(11.9505528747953,-1.89280448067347,13.3750217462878));
#402=CARTESIAN_POINT('',(12.0732294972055,0.791375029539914,13.5520639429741));
#403=CARTESIAN_POINT('',(11.6004559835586,3.43615408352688,13.7291812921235));
#404=CARTESIAN_POINT('',(10.5571319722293,5.91236418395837,13.9062408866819));
#405=CARTESIAN_POINT('',(8.99065632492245,8.09513602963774,14.0833359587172));
#406=CARTESIAN_POINT('',(6.98362953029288,9.8816883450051,14.2604258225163));
#407=CARTESIAN_POINT('',(4.62983172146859,11.1772528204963,14.4374752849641));
#408=CARTESIAN_POINT('',(2.0488845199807,11.9251576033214,14.6146128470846));
#409=CARTESIAN_POINT('',(-0.632664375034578,12.0814265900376,14.7916559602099));
#410=CARTESIAN_POINT('',(-3.28541945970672,11.6466721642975,14.9687246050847));
#411=CARTESIAN_POINT('',(-5.76888143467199,10.6292490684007,15.1458635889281));
#412=CARTESIAN_POINT('',(-7.9986345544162,9.10992743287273,15.3230263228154));
#413=CARTESIAN_POINT('',(-9.13912102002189,7.73824109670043,15.4410756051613));
#414=CARTESIAN_POINT('',(-9.70839594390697,7.05356253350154,15.5000000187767));
#415=CARTESIAN_POINT('',(9.,0.,-1.5));
#416=CARTESIAN_POINT('',(8.95600473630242,0.666533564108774,-1.44093653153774));
#417=CARTESIAN_POINT('',(8.86786480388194,2.00186419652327,-1.32260901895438));
#418=CARTESIAN_POINT('',(8.18736473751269,3.90663796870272,-1.14707491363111));
#419=CARTESIAN_POINT('',(7.12614541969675,5.61932126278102,-0.968469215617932));
#420=CARTESIAN_POINT('',(5.71346551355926,7.04923305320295,-0.792354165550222));
#421=CARTESIAN_POINT('',(4.00933201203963,8.14057513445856,-0.614090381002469));
#422=CARTESIAN_POINT('',(2.12113854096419,8.82236922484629,-0.438422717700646));
#423=CARTESIAN_POINT('',(0.116948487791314,9.07461417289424,-0.260207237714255));
#424=CARTESIAN_POINT('',(-1.88636066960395,8.87455577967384,-0.0835441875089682));
#425=CARTESIAN_POINT('',(-3.79800589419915,8.24289655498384,0.0931088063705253));
#426=CARTESIAN_POINT('',(-5.52556446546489,7.19638944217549,0.271145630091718));
#427=CARTESIAN_POINT('',(-6.97482782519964,5.80607811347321,0.446917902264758));
#428=CARTESIAN_POINT('',(-8.08677104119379,4.11570779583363,0.625560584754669));
#429=CARTESIAN_POINT('',(-8.79398597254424,2.23728374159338,0.801121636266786));
#430=CARTESIAN_POINT('',(-9.07191476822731,0.234219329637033,0.979557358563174));
#431=CARTESIAN_POINT('',(-8.8991084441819,-1.76852434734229,1.15571620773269));
#432=CARTESIAN_POINT('',(-8.29104752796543,-3.69150172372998,1.33309607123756));
#433=CARTESIAN_POINT('',(-7.26874005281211,-5.42971020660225,1.51047533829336));
#434=CARTESIAN_POINT('',(-5.89655636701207,-6.89903558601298,1.68663596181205));
#435=CARTESIAN_POINT('',(-4.22136143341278,-8.03158628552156,1.86506834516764));
#436=CARTESIAN_POINT('',(-2.35270843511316,-8.76438373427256,2.04063032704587));
#437=CARTESIAN_POINT('',(-0.352199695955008,-9.06755881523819,2.21928278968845));
#438=CARTESIAN_POINT('',(1.65067716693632,-8.92217601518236,2.39504466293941));
#439=CARTESIAN_POINT('',(3.58430549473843,-8.33760891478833,2.57304985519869));
#440=CARTESIAN_POINT('',(5.33285918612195,-7.34012806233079,2.74976226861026));
#441=CARTESIAN_POINT('',(6.82230989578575,-5.98547260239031,2.92647615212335));
#442=CARTESIAN_POINT('',(7.97489176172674,-4.32676372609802,3.10448016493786));
#443=CARTESIAN_POINT('',(8.73337282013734,-2.46719919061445,3.28024284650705));
#444=CARTESIAN_POINT('',(9.06164184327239,-0.470702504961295,3.45889503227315));
#445=CARTESIAN_POINT('',(8.94369010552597,1.53297606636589,3.63445673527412));
#446=CARTESIAN_POINT('',(8.38287241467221,3.47591041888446,3.81288994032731));
#447=CARTESIAN_POINT('',(7.41041652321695,5.2352209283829,3.98904929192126));
#448=CARTESIAN_POINT('',(6.07277966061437,6.74462739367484,4.16642969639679));
#449=CARTESIAN_POINT('',(4.43186240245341,7.91675002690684,4.3438086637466));
#450=CARTESIAN_POINT('',(2.58068172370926,8.70092817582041,4.51996925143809));
#451=CARTESIAN_POINT('',(0.589665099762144,9.05420154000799,4.69840168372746));
#452=CARTESIAN_POINT('',(-1.41548991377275,8.96359568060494,4.87396366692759));
#453=CARTESIAN_POINT('',(-3.36635799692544,8.4268796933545,5.05261612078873));
#454=CARTESIAN_POINT('',(-5.13694454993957,7.47942248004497,5.22837799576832));
#455=CARTESIAN_POINT('',(-6.66563706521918,6.15891636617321,5.40638318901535));
#456=CARTESIAN_POINT('',(-7.85730833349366,4.53647140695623,5.58309560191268));
#457=CARTESIAN_POINT('',(-8.66700124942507,2.69311788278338,5.75980948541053));
#458=CARTESIAN_POINT('',(-9.04527949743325,0.709014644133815,5.93781349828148));
#459=CARTESIAN_POINT('',(-8.98183338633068,-1.2982841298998,6.11357617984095));
#460=CARTESIAN_POINT('',(-8.4696737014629,-3.25569364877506,6.29222836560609));
#461=CARTESIAN_POINT('',(-7.54694993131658,-5.03816981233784,6.46779006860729));
#462=CARTESIAN_POINT('',(-6.24435488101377,-6.58502355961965,6.64622327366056));
#463=CARTESIAN_POINT('',(-4.64039616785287,-7.7967002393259,6.82238262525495));
#464=CARTESIAN_POINT('',(-2.80447316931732,-8.63154573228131,6.9997630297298));
#465=CARTESIAN_POINT('',(-0.828675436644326,-9.03491186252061,7.17714199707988));
#466=CARTESIAN_POINT('',(1.18141625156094,-8.99835123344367,7.35330258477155));
#467=CARTESIAN_POINT('',(3.14398966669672,-8.51126309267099,7.5317350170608));
#468=CARTESIAN_POINT('',(4.93893719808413,-7.61292050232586,7.70729700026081));
#469=CARTESIAN_POINT('',(6.50284181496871,-6.32911651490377,7.88594945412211));
#470=CARTESIAN_POINT('',(7.73498755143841,-4.743408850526,8.0617113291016));
#471=CARTESIAN_POINT('',(8.59441943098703,-2.91529122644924,8.23971652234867));
#472=CARTESIAN_POINT('',(9.02315748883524,-0.948417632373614,8.41642893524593));
#473=CARTESIAN_POINT('',(9.01308934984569,1.06490138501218,8.59314281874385));
#474=CARTESIAN_POINT('',(8.55165623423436,3.03132951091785,8.77114683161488));
#475=CARTESIAN_POINT('',(7.67725336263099,4.83928232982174,8.94690951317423));
#476=CARTESIAN_POINT('',(6.41322203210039,6.41915079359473,9.12556169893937));
#477=CARTESIAN_POINT('',(4.8452735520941,7.67221822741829,9.30112340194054));
#478=CARTESIAN_POINT('',(3.02613166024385,8.55552630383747,9.47955660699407));
#479=CARTESIAN_POINT('',(1.0680091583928,9.01005924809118,9.65571595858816));
#480=CARTESIAN_POINT('',(-0.948752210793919,9.02599139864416,9.83309636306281));
#481=CARTESIAN_POINT('',(-2.91779704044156,8.59085535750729,10.0104753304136));
#482=CARTESIAN_POINT('',(-4.73923662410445,7.73987761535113,10.1866359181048));
#483=CARTESIAN_POINT('',(-6.33402005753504,6.49664993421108,10.365068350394));
#484=CARTESIAN_POINT('',(-7.60839737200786,4.94590220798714,10.5406303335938));
#485=CARTESIAN_POINT('',(-8.51492520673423,3.13699159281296,10.7192827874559));
#486=CARTESIAN_POINT('',(-8.99558093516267,1.18721673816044,10.8950446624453));
#487=CARTESIAN_POINT('',(-9.03714859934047,-0.832414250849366,11.0730498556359));
#488=CARTESIAN_POINT('',(-8.6288207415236,-2.80362616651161,11.2497622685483));
#489=CARTESIAN_POINT('',(-7.80073241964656,-4.63878952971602,11.4264761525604));
#490=CARTESIAN_POINT('',(-6.57937391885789,-6.24752925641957,11.6044801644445));
#491=CARTESIAN_POINT('',(-5.04520649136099,-7.54352464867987,11.7802428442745));
#492=CARTESIAN_POINT('',(-3.24786600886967,-8.4726784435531,11.9588950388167));
#493=CARTESIAN_POINT('',(-1.3058053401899,-8.97967041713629,12.1344567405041));
#494=CARTESIAN_POINT('',(0.715337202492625,-9.04670085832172,12.3128898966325));
#495=CARTESIAN_POINT('',(2.68904630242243,-8.66549714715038,12.4890492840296));
#496=CARTESIAN_POINT('',(4.53792969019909,-7.85976098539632,12.6664299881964));
#497=CARTESIAN_POINT('',(6.15975598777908,-6.66136208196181,12.8438084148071));
#498=CARTESIAN_POINT('',(7.47760029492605,-5.14310898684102,13.019968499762));
#499=CARTESIAN_POINT('',(8.42884024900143,-3.35870625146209,13.1984034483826));
#500=CARTESIAN_POINT('',(8.96229524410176,-1.42369474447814,13.3739647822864));
#501=CARTESIAN_POINT('',(9.05470368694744,0.597547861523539,13.5526077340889));
#502=CARTESIAN_POINT('',(8.70075580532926,2.57427189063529,13.7283791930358));
#503=CARTESIAN_POINT('',(7.91726960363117,4.43616607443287,13.906417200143));
#504=CARTESIAN_POINT('',(6.7425161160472,6.07084149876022,14.0830687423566));
#505=CARTESIAN_POINT('',(5.23944952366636,7.41071408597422,14.2597332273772));
#506=CARTESIAN_POINT('',(3.46938843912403,8.38355550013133,14.4379474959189));
#507=CARTESIAN_POINT('',(1.54133593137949,8.94324690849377,14.6136161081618));
#508=CARTESIAN_POINT('',(-0.478870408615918,9.06078371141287,14.791879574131));
#509=CARTESIAN_POINT('',(-2.46234115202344,8.73523920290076,14.967994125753));
#510=CARTESIAN_POINT('',(-4.32710193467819,7.97204086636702,15.1466009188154));
#511=CARTESIAN_POINT('',(-5.9979698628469,6.83246277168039,15.3221336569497));
#512=CARTESIAN_POINT('',(-6.85405017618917,5.80369284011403,15.4404617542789));
#513=CARTESIAN_POINT('',(-7.28136349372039,5.29018133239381,15.4995253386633));
#514=CARTESIAN_POINT('',(9.,0.,1.5));
#515=CARTESIAN_POINT('',(8.95613006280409,0.666589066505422,1.55906347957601));
#516=CARTESIAN_POINT('',(8.86824120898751,2.00203089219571,1.67739101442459));
#517=CARTESIAN_POINT('',(8.18631485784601,3.90604188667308,1.85292494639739));
#518=CARTESIAN_POINT('',(7.12631531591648,5.61950210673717,2.03153082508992));
#519=CARTESIAN_POINT('',(5.71303407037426,7.04868989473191,2.20764578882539));
#520=CARTESIAN_POINT('',(4.00960298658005,8.14101417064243,2.38590964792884));
#521=CARTESIAN_POINT('',(2.12085576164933,8.82146778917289,2.56157720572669));
#522=CARTESIAN_POINT('',(0.117062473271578,9.07482582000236,2.73979278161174));
#523=CARTESIAN_POINT('',(-1.88643189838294,8.87432655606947,2.91645580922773));
#524=CARTESIAN_POINT('',(-3.7976280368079,8.2423546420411,3.09310875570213));
#525=CARTESIAN_POINT('',(-5.52581519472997,7.19659944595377,3.27114566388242));
#526=CARTESIAN_POINT('',(-6.97401793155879,5.8054683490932,3.44691781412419));
#527=CARTESIAN_POINT('',(-8.08727688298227,4.11597402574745,3.62556062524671));
#528=CARTESIAN_POINT('',(-8.79304860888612,2.23701102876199,3.8011215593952));
#529=CARTESIAN_POINT('',(-9.07231067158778,0.234316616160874,3.97955738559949));
#530=CARTESIAN_POINT('',(-8.89855852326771,-1.76851805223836,4.15571617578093));
#531=CARTESIAN_POINT('',(-8.29087902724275,-3.69129114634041,4.33309606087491));
#532=CARTESIAN_POINT('',(-7.26872928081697,-5.42982858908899,4.51047535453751));
#533=CARTESIAN_POINT('',(-5.89605388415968,-6.89831262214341,4.68663588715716));
#534=CARTESIAN_POINT('',(-4.22156158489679,-8.03204045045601,4.86506838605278));
#535=CARTESIAN_POINT('',(-2.35244426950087,-8.76336617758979,5.04063023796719));
#536=CARTESIAN_POINT('',(-0.352270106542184,-9.06809934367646,5.21928282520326));
#537=CARTESIAN_POINT('',(1.65060167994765,-8.92137666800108,5.39504460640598));
#538=CARTESIAN_POINT('',(3.58425463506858,-8.33777940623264,5.57304986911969));
#539=CARTESIAN_POINT('',(5.33281038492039,-7.33986768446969,5.74976226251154));
#540=CARTESIAN_POINT('',(6.82177202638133,-5.98515297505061,5.926476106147));
#541=CARTESIAN_POINT('',(7.97520823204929,-4.32685374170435,6.10448019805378));
#542=CARTESIAN_POINT('',(8.73237619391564,-2.46696982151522,6.28024275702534));
#543=CARTESIAN_POINT('',(9.06221330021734,-0.470740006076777,6.45889507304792));
#544=CARTESIAN_POINT('',(8.94272469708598,1.53284441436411,6.63445665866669));
#545=CARTESIAN_POINT('',(8.38327297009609,3.47598224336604,6.81288996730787));
#546=CARTESIAN_POINT('',(7.40991650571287,5.23499130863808,6.98904925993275));
#547=CARTESIAN_POINT('',(6.07271156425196,6.7443667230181,7.16642968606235));
#548=CARTESIAN_POINT('',(4.43180440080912,7.91685379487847,7.34380867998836));
#549=CARTESIAN_POINT('',(2.58051673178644,8.70006329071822,7.51996917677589));
#550=CARTESIAN_POINT('',(0.589663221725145,9.05469785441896,7.6984017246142));
#551=CARTESIAN_POINT('',(-1.41531736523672,8.96255865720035,7.87396357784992));
#552=CARTESIAN_POINT('',(-3.36651352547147,8.42740212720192,8.05261615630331));
#553=CARTESIAN_POINT('',(-5.13655046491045,7.47872294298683,8.2283779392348));
#554=CARTESIAN_POINT('',(-6.66565994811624,6.15909280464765,8.40638320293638));
#555=CARTESIAN_POINT('',(-7.85715784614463,4.53625338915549,8.58309559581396));
#556=CARTESIAN_POINT('',(-8.66637987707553,2.69304465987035,8.75980943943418));
#557=CARTESIAN_POINT('',(-9.04560522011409,0.708968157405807,8.93781353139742));
#558=CARTESIAN_POINT('',(-8.98082963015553,-1.29808830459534,9.11357609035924));
#559=CARTESIAN_POINT('',(-8.470211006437,-3.2558918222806,9.29222840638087));
#560=CARTESIAN_POINT('',(-7.5461215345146,-5.03765687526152,9.46778999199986));
#561=CARTESIAN_POINT('',(-6.24469159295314,-6.58525209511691,9.64622330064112));
#562=CARTESIAN_POINT('',(-4.64003277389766,-7.79628709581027,9.82238259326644));
#563=CARTESIAN_POINT('',(-2.80451698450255,-8.63127990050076,9.99976301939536));
#564=CARTESIAN_POINT('',(-0.828580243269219,-9.03498306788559,10.1771420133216));
#565=CARTESIAN_POINT('',(1.18121519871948,-8.99749401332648,10.3533025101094));
#566=CARTESIAN_POINT('',(3.14419325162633,-8.51171573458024,10.5317350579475));
#567=CARTESIAN_POINT('',(4.93835777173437,-7.61204331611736,10.7072969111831));
#568=CARTESIAN_POINT('',(6.50319639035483,-6.32953052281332,10.8859494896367));
#569=CARTESIAN_POINT('',(7.73434300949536,-4.7429300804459,11.0617112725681));
#570=CARTESIAN_POINT('',(8.59451209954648,-2.91544310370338,11.2397165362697));
#571=CARTESIAN_POINT('',(9.02293133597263,-0.948279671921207,11.4164289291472));
#572=CARTESIAN_POINT('',(9.01249191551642,1.06471554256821,11.5931427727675));
#573=CARTESIAN_POINT('',(8.55193488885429,3.03150446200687,11.7711468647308));
#574=CARTESIAN_POINT('',(7.67641603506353,4.83869517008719,11.9469094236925));
#575=CARTESIAN_POINT('',(6.41363228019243,6.41955037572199,12.1255617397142));
#576=CARTESIAN_POINT('',(4.84472540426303,7.67141269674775,12.3011233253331));
#577=CARTESIAN_POINT('',(3.02634630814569,8.55587203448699,12.4795566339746));
#578=CARTESIAN_POINT('',(1.06784522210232,9.00953401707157,12.6557159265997));
#579=CARTESIAN_POINT('',(-0.948604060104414,9.0257663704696,12.8330963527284));
#580=CARTESIAN_POINT('',(-2.91791296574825,8.59088168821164,13.0104753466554));
#581=CARTESIAN_POINT('',(-4.73870429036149,7.73917628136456,13.1866358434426));
#582=CARTESIAN_POINT('',(-6.33439014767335,6.49698063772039,13.3650683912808));
#583=CARTESIAN_POINT('',(-7.60751125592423,4.94533653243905,13.5406302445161));
#584=CARTESIAN_POINT('',(-8.51541751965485,3.13722558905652,13.7192828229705));
#585=CARTESIAN_POINT('',(-8.99479738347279,1.18704151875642,13.8950446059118));
#586=CARTESIAN_POINT('',(-9.03729503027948,-0.832313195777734,14.0730498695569));
#587=CARTESIAN_POINT('',(-8.62855802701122,-2.8036602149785,14.2497622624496));
#588=CARTESIAN_POINT('',(-7.80026222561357,-4.638376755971,14.4264761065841));
#589=CARTESIAN_POINT('',(-6.57955732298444,-6.24780242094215,14.6044801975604));
#590=CARTESIAN_POINT('',(-5.04468037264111,-7.54264767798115,14.7802427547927));
#591=CARTESIAN_POINT('',(-3.24807826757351,-8.47321034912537,14.9588950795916));
#592=CARTESIAN_POINT('',(-1.30563222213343,-8.97871158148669,15.1344566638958));
#593=CARTESIAN_POINT('',(0.715281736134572,-9.04710395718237,15.3128899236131));
#594=CARTESIAN_POINT('',(2.68898242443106,-8.66495064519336,15.4890492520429));
#595=CARTESIAN_POINT('',(4.53770295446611,-7.85961594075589,15.6664299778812));
#596=CARTESIAN_POINT('',(6.15987244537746,-6.66133875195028,15.8438084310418));
#597=CARTESIAN_POINT('',(7.4768281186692,-5.14268434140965,16.0199684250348));
#598=CARTESIAN_POINT('',(8.42931455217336,-3.35885867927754,16.1984034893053));
#599=CARTESIAN_POINT('',(8.96125670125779,-1.42353857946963,16.373964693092));
#600=CARTESIAN_POINT('',(9.05523970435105,0.597534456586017,16.5526077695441));
#601=CARTESIAN_POINT('',(8.69997071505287,2.57411299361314,16.7283791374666));
#602=CARTESIAN_POINT('',(7.91747612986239,4.43614881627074,16.9064172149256));
#603=CARTESIAN_POINT('',(6.74223751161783,6.0707485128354,17.083068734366));
#604=CARTESIAN_POINT('',(5.23914136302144,7.41008488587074,17.2597331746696));
#605=CARTESIAN_POINT('',(3.46950590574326,8.38400895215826,17.4379475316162));
#606=CARTESIAN_POINT('',(1.54121678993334,8.9422606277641,17.6136160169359));
#607=CARTESIAN_POINT('',(-0.478875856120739,9.06099878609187,17.7918796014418));
#608=CARTESIAN_POINT('',(-2.46217976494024,8.73453236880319,17.9679940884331));
#609=CARTESIAN_POINT('',(-4.32737280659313,7.97271977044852,18.1466009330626));
#610=CARTESIAN_POINT('',(-5.99744676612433,6.83174631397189,18.3221335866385));
#611=CARTESIAN_POINT('',(-6.85361984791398,5.80326817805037,18.4404617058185));
#612=CARTESIAN_POINT('',(-7.28097947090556,5.28990232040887,18.4995253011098));
#613=CARTESIAN_POINT('',(12.,0.,1.5));
#614=CARTESIAN_POINT('',(11.9418927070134,0.888508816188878,1.55892430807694));
#615=CARTESIAN_POINT('',(11.8254807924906,2.66854376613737,1.67697302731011));
#616=CARTESIAN_POINT('',(10.9146193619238,5.20828516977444,1.85413695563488));
#617=CARTESIAN_POINT('',(9.50351753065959,7.49108137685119,2.0312750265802));
#618=CARTESIAN_POINT('',(7.612969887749,9.4020238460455,2.20834408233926));
#619=CARTESIAN_POINT('',(5.35173785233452,10.8517466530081,2.3853875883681));
#620=CARTESIAN_POINT('',(2.8241644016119,11.7636999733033,2.56252409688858));
#621=CARTESIAN_POINT('',(0.158422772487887,12.0990888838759,2.73957486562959));
#622=CARTESIAN_POINT('',(-2.51533122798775,11.8334460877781,2.91666327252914));
#623=CARTESIAN_POINT('',(-5.0656074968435,10.9883084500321,3.09375974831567));
#624=CARTESIAN_POINT('',(-7.36509357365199,9.59829820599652,3.27081824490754));
#625=CARTESIAN_POINT('',(-9.30210830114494,7.73654640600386,3.44793628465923));
#626=CARTESIAN_POINT('',(-10.7805494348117,5.49293821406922,3.62497834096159));
#627=CARTESIAN_POINT('',(-11.7258602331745,2.97799692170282,3.8021033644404));
#628=CARTESIAN_POINT('',(-12.0958270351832,0.31675811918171,3.97915157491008));
#629=CARTESIAN_POINT('',(-11.8653071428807,-2.3601936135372,4.15625805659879));
#630=CARTESIAN_POINT('',(-11.0539405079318,-4.92146957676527,4.33333370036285));
#631=CARTESIAN_POINT('',(-9.69359276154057,-7.2386166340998,4.51040787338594));
#632=CARTESIAN_POINT('',(-7.85793807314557,-9.20036793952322,4.68751556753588));
#633=CARTESIAN_POINT('',(-5.63336414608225,-10.7073455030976,4.86456316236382));
#634=CARTESIAN_POINT('',(-3.13134399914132,-11.6862177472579,5.04168825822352));
#635=CARTESIAN_POINT('',(-0.475027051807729,-12.0903507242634,5.21873018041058));
#636=CARTESIAN_POINT('',(2.2046758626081,-11.8952806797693,5.39584853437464));
#637=CARTESIAN_POINT('',(4.77640624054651,-11.1174868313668,5.57290865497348));
#638=CARTESIAN_POINT('',(7.11097475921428,-9.7873304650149,5.74999960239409));
#639=CARTESIAN_POINT('',(9.09701650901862,-7.97795538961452,5.92709199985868));
#640=CARTESIAN_POINT('',(10.6323245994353,-5.77282598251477,6.10415094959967));
#641=CARTESIAN_POINT('',(11.6446337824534,-3.28417762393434,6.28127007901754));
#642=CARTESIAN_POINT('',(12.0827018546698,-0.633204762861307,6.45831173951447));
#643=CARTESIAN_POINT('',(11.9233675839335,2.04880154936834,6.63543656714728));
#644=CARTESIAN_POINT('',(11.1789246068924,4.63044315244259,6.81248492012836));
#645=CARTESIAN_POINT('',(9.87952006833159,6.98219921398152,6.98959141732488));
#646=CARTESIAN_POINT('',(8.09653525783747,8.9920289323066,7.16666702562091));
#647=CARTESIAN_POINT('',(5.91132700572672,10.5555447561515,7.34374120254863));
#648=CARTESIAN_POINT('',(3.43645684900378,11.6010656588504,7.52084890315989));
#649=CARTESIAN_POINT('',(0.791264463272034,12.0729424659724,7.69789649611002));
#650=CARTESIAN_POINT('',(-1.89258789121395,11.9495234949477,7.87502159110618));
#651=CARTESIAN_POINT('',(-4.48362986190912,11.2382958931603,8.05206351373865));
#652=CARTESIAN_POINT('',(-6.85231815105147,9.97015717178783,8.22918186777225));
#653=CARTESIAN_POINT('',(-8.88535349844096,8.21359015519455,8.40624198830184));
#654=CARTESIAN_POINT('',(-10.4770646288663,6.04887728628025,8.58333293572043));
#655=CARTESIAN_POINT('',(-11.5554649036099,3.5881349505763,8.76042533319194));
#656=CARTESIAN_POINT('',(-12.0611317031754,0.949182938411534,8.93748428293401));
#657=CARTESIAN_POINT('',(-11.9736976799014,-1.73605370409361,9.11460341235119));
#658=CARTESIAN_POINT('',(-11.2956449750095,-4.33601625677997,9.29164507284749));
#659=CARTESIAN_POINT('',(-10.0592156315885,-6.72134385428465,9.46876990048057));
#660=CARTESIAN_POINT('',(-8.32908489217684,-8.77699857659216,9.64581825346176));
#661=CARTESIAN_POINT('',(-6.18547441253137,-10.3969192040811,9.8229247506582));
#662=CARTESIAN_POINT('',(-3.7391653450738,-11.5077847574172,10.0000003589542));
#663=CARTESIAN_POINT('',(-1.10693909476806,-12.0473232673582,10.177074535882));
#664=CARTESIAN_POINT('',(1.57921895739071,-11.9958337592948,10.3541822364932));
#665=CARTESIAN_POINT('',(4.18765203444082,-11.3510180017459,10.5312298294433));
#666=CARTESIAN_POINT('',(6.5892741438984,-10.1466480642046,10.7083549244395));
#667=CARTESIAN_POINT('',(8.66702643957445,-8.44303760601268,10.885396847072));
#668=CARTESIAN_POINT('',(10.3151323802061,-6.3211029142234,11.0625152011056));
#669=CARTESIAN_POINT('',(11.4579424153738,-3.88948912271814,11.2395753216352));
#670=CARTESIAN_POINT('',(12.0315748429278,-1.26451827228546,11.4166662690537));
#671=CARTESIAN_POINT('',(12.0158684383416,1.42210661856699,11.5937586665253));
#672=CARTESIAN_POINT('',(11.4044595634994,4.03858245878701,11.7708176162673));
#673=CARTESIAN_POINT('',(10.2324004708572,6.45610557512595,11.9479367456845));
#674=CARTESIAN_POINT('',(8.55546846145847,8.55550067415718,12.1249784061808));
#675=CARTESIAN_POINT('',(6.45573391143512,10.2317047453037,12.3021032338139));
#676=CARTESIAN_POINT('',(4.03907073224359,11.4059312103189,12.4791515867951));
#677=CARTESIAN_POINT('',(1.42190403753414,12.0139174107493,12.6562580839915));
#678=CARTESIAN_POINT('',(-1.26474022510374,12.0337400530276,12.8333336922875));
#679=CARTESIAN_POINT('',(-3.88884864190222,11.4560101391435,13.0104078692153));
#680=CARTESIAN_POINT('',(-6.32183345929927,10.3164132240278,13.1875155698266));
#681=CARTESIAN_POINT('',(-8.44248545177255,8.66639940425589,13.3645631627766));
#682=CARTESIAN_POINT('',(-10.1466150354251,6.58932500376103,13.5416882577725));
#683=CARTESIAN_POINT('',(-11.3518154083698,4.18790141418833,13.7187301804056));
#684=CARTESIAN_POINT('',(-11.9943665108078,1.57907253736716,13.8958485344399));
#685=CARTESIAN_POINT('',(-12.0493489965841,-1.10713991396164,14.0729086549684));
#686=CARTESIAN_POINT('',(-11.5057164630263,-3.73848743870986,14.24999960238));
#687=CARTESIAN_POINT('',(-10.3986191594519,-6.18645303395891,14.4270919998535));
#688=CARTESIAN_POINT('',(-8.77585275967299,-8.32804026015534,14.6041509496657));
#689=CARTESIAN_POINT('',(-6.72182826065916,-10.0598381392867,14.7812700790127));
#690=CARTESIAN_POINT('',(-4.33597372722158,-11.2956612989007,14.9583117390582));
#691=CARTESIAN_POINT('',(-1.73599715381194,-11.9729109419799,15.1354365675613));
#692=CARTESIAN_POINT('',(0.949335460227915,-12.0626747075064,15.3124849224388));
#693=CARTESIAN_POINT('',(3.58752645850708,-11.5536001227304,15.4895914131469));
#694=CARTESIAN_POINT('',(6.04996074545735,-10.4789525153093,15.6666670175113));
#695=CARTESIAN_POINT('',(8.21221908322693,-8.88384871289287,15.8437412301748));
#696=CARTESIAN_POINT('',(9.9713452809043,-6.85319072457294,16.0208489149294));
#697=CARTESIAN_POINT('',(11.2375374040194,-4.48328224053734,16.1978963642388));
#698=CARTESIAN_POINT('',(11.9495143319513,-1.89264831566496,16.3750216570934));
#699=CARTESIAN_POINT('',(12.0737655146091,0.791361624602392,16.5520639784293));
#700=CARTESIAN_POINT('',(11.5996708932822,3.43599518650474,16.7291812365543));
#701=CARTESIAN_POINT('',(10.5573384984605,5.91234692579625,16.9062409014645));
#702=CARTESIAN_POINT('',(8.99037772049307,8.09504304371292,17.0833359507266));
#703=CARTESIAN_POINT('',(6.98332136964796,9.88105914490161,17.2604257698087));
#704=CARTESIAN_POINT('',(4.62994918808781,11.1777062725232,17.4374753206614));
#705=CARTESIAN_POINT('',(2.04876537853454,11.9241713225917,17.6146127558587));
#706=CARTESIAN_POINT('',(-0.632669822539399,12.0816416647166,17.7916559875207));
#707=CARTESIAN_POINT('',(-3.28525807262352,11.6459653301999,17.9687245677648));
#708=CARTESIAN_POINT('',(-5.76915230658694,10.6299279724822,18.1458636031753));
#709=CARTESIAN_POINT('',(-7.99811145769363,9.10921097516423,18.3230262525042));
#710=CARTESIAN_POINT('',(-9.13869069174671,7.73781643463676,18.4410755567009));
#711=CARTESIAN_POINT('',(-9.70801192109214,7.0532835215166,18.4999999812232));
#712=(BOUNDED_SURFACE() B_SPLINE_SURFACE(3,3,((#19,#20,#21,#22,#23,#24,#25,#26,#27,#28,#29,#30,
#31,#32,#33,#34,#35,#36,#37,#38,#39,#40,#41,#42,#43,#44,#45,#46,#47,#48,#49,#50,#51,#52,#53,#54,
#55,#56,#57,#58,#59,#60,#61,#62,#63,#64,#65,#66,#67,#68,#69,#70,#71,#72,#73,#74,#75,#76,#77,#78,
#79,#80,#81,#82,#83,#84,#85,#86,#87,#88,#89,#90,#91,#92,#93,#94,#95,#96,#97,#98,#99,#100,#101,
#102,#103,#104,#105,#106,#107,#108,#109,#110,#111,#112,#113,#114,#115,#116,#117),(#118,#119,
#120,#121,#122,#123,#124,#125,#126,#127,#128,#129,#130,#131,#132,#133,#134,#135,#136,#137,#138,
#139,#140,#141,#142,#143,#144,#145,#146,#147,#148,#149,#150,#151,#152,#153,#154,#155,#156,#157,
#158,#159,#160,#161,#162,#163,#164,#165,#166,#167,#168,#169,#170,#171,#172,#173,#174,#175,#176,
#177,#178,#179,#180,#181,#182,#183,#184,#185,#186,#187,#188,#189,#190,#191,#192,#193,#194,#195,
#196,#197,#198,#199,#200,#201,#202,#203,#204,#205,#206,#207,#208,#209,#210,#211,#212,#213,#214,
#215,#216),(#217,#218,#219,#220,#221,#222,#223,#224,#225,#226,#227,#228,#229,#230,#231,#232,
#233,#234,#235,#236,#237,#238,#239,#240,#241,#242,#243,#244,#245,#246,#247,#248,#249,#250,#251,
#252,#253,#254,#255,#256,#257,#258,#259,#260,#261,#262,#263,#264,#265,#266,#267,#268,#269,#270,
#271,#272,#273,#274,#275,#276,#277,#278,#279,#280,#281,#282,#283,#284,#285,#286,#287,#288,#289,
#290,#291,#292,#293,#294,#295,#296,#297,#298,#299,#300,#301,#302,#303,#304,#305,#306,#307,#308,
#309,#310,#311,#312,#313,#314,#315),(#316,#317,#318,#319,#320,#321,#322,#323,#324,#325,#326,
#327,#328,#329,#330,#331,#332,#333,#334,#335,#336,#337,#338,#339,#340,#341,#342,#343,#344,#345,
#346,#347,#348,#349,#350,#351,#352,#353,#354,#355,#356,#357,#358,#359,#360,#361,#362,#363,#364,
#365,#366,#367,#368,#369,#370,#371,#372,#373,#374,#375,#376,#377,#378,#379,#380,#381,#382,#383,
#384,#385,#386,#387,#388,#389,#390,#391,#392,#393,#394,#395,#396,#397,#398,#399,#400,#401,#402,
#403,#404,#405,#406,#407,#408,#409,#410,#411,#412,#413,#414),(#415,#416,#417,#418,#419,#420,
#421,#422,#423,#424,#425,#426,#427,#428,#429,#430,#431,#432,#433,#434,#435,#436,#437,#438,#439,
#440,#441,#442,#443,#444,#445,#446,#447,#448,#449,#450,#451,#452,#453,#454,#455,#456,#457,#458,
#459,#460,#461,#462,#463,#464,#465,#466,#467,#468,#469,#470,#471,#472,#473,#474,#475,#476,#477,
#478,#479,#480,#481,#482,#483,#484,#485,#486,#487,#488,#489,#490,#491,#492,#493,#494,#495,#496,
#497,#498,#499,#500,#501,#502,#503,#504,#505,#506,#507,#508,#509,#510,#511,#512,#513),(#514,
#515,#516,#517,#518,#519,#520,#521,#522,#523,#524,#525,#526,#527,#528,#529,#530,#531,#532,#533,
#534,#535,#536,#537,#538,#539,#540,#541,#542,#543,#544,#545,#546,#547,#548,#549,#550,#551,#552,
#553,#554,#555,#556,#557,#558,#559,#560,#561,#562,#563,#564,#565,#566,#567,#568,#569,#570,#571,
#572,#573,#574,#575,#576,#577,#578,#579,#580,#581,#582,#583,#584,#585,#586,#587,#588,#589,#590,
#591,#592,#593,#594,#595,#596,#597,#598,#599,#600,#601,#602,#603,#604,#605,#606,#607,#608,#609,
#610,#611,#612),(#613,#614,#615,#616,#617,#618,#619,#620,#621,#622,#623,#624,#625,#626,#627,
#628,#629,#630,#631,#632,#633,#634,#635,#636,#637,#638,#639,#640,#641,#642,#643,#644,#645,#646,
#647,#648,#649,#650,#651,#652,#653,#654,#655,#656,#657,#658,#659,#660,#661,#662,#663,#664,#665,
#666,#667,#668,#669,#670,#671,#672,#673,#674,#675,#676,#677,#678,#679,#680,#681,#682,#683,#684,
#685,#686,#687,#688,#689,#690,#691,#692,#693,#694,#695,#696,#697,#698,#699,#700,#701,#702,#703,
#704,#705,#706,#707,#708,#709,#710,#711)),.UNSPECIFIED.,.T.,.F.,
.F.) B_SPLINE_SURFACE_WITH_KNOTS((4,3,4),(4,1,1,1,1,1,1,1,1,1,1,1,1,1,1,1,1,1,1,1,1,1,1,1,1,1,1,
1,1,1,1,1,1,1,1,1,1,1,1,1,1,1,1,1,1,1,1,1,1,1,1,1,1,1,1,1,1,1,1,1,1,1,1,1,1,1,1,1,1,1,1,1,1,1,1,
1,1,1,1,1,1,1,1,1,1,1,1,1,1,1,1,1,1,1,1,1,4),(0.,0.5,1.),(0.,0.0103999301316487,
0.0208351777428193,0.0312527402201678,0.0416652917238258,0.052083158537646,0.0624994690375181,
0.0729165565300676,0.0833331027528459,0.093749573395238,0.104166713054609,0.114582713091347,
0.125000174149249,0.135416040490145,0.145833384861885,0.156249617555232,0.166666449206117,
0.177083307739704,0.187499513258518,0.197916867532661,0.208332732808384,0.218750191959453,
0.229166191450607,0.239583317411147,0.249999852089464,0.260416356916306,0.270833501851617,
0.281249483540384,0.291666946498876,0.302082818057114,0.312500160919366,0.322916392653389,
0.333333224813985,0.343750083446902,0.35416628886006,0.36458364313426,0.374999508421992,
0.385416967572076,0.395832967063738,0.40625009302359,0.416666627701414,0.427083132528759,
0.437500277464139,0.447916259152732,0.458333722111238,0.468749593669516,0.479166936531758,
0.489583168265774,0.500000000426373,0.51041685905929,0.520833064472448,0.531250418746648,
0.54166628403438,0.552083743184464,0.562499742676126,0.572916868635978,0.583333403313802,
0.593749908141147,0.604167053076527,0.61458303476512,0.625000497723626,0.635416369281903,
0.645833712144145,0.656249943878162,0.666666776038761,0.677083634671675,0.687499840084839,
0.697917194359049,0.708333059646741,0.71875051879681,0.729166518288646,0.73958364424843,
0.750000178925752,0.760416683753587,0.770833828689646,0.781249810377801,0.791667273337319,
0.802083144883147,0.812500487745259,0.822916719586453,0.833333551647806,0.843750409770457,
0.854166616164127,0.864583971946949,0.874999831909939,0.885417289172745,0.895833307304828,
0.906250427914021,0.916666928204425,0.927083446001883,0.937500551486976,0.947916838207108,
0.958334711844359,0.968747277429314,0.97916482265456,0.989600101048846,1.),
.UNSPECIFIED.) GEOMETRIC_REPRESENTATION_ITEM() RATIONAL_B_SPLINE_SURFACE(((1.,1.,1.,1.,1.,1.,1.,
1.,1.,1.,0.999999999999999,1.,1.,1.,1.,1.,1.,1.,1.,1.,1.,1.,1.,1.,1.,1.,1.,1.,1.,1.,1.,1.,1.,1.,
1.,1.,1.,1.,1.,1.,1.,1.,1.,1.,1.,1.,1.,1.,1.,1.,1.,1.,1.,1.,1.,1.,1.,1.,1.,1.,1.,1.,1.,1.,1.,1.,
1.,1.,1.,1.,1.,1.,1.,1.,1.,1.,1.,1.,1.,1.,1.,1.,1.,1.,1.,1.,1.,1.,1.,1.,1.,1.,1.,1.,1.,1.,1.,1.,
1.),(0.333333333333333,0.333333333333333,0.333333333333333,0.333333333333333,0.333333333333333,
0.333333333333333,0.333333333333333,0.333333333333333,0.333333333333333,0.333333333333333,
0.333333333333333,0.333333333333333,0.333333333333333,0.333333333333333,0.333333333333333,
0.333333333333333,0.333333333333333,0.333333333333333,0.333333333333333,0.333333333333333,
0.333333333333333,0.333333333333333,0.333333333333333,0.333333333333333,0.333333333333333,
0.333333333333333,0.333333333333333,0.333333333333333,0.333333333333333,0.333333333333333,
0.333333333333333,0.333333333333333,0.333333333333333,0.333333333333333,0.333333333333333,
0.333333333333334,0.333333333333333,0.333333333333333,0.333333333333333,0.333333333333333,
0.333333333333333,0.333333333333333,0.333333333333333,0.333333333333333,0.333333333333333,
0.333333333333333,0.333333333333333,0.333333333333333,0.333333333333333,0.333333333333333,
0.333333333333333,0.333333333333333,0.333333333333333,0.333333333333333,0.333333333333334,
0.333333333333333,0.333333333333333,0.333333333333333,0.333333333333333,0.333333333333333,
0.333333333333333,0.333333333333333,0.333333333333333,0.333333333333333,0.333333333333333,
0.333333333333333,0.333333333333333,0.333333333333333,0.333333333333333,0.333333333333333,
0.333333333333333,0.333333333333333,0.333333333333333,0.333333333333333,0.333333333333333,
0.333333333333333,0.333333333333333,0.333333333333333,0.333333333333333,0.333333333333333,
0.333333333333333,0.333333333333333,0.333333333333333,0.333333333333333,0.333333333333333,
0.333333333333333,0.333333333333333,0.333333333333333,0.333333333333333,0.333333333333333,
0.333333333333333,0.333333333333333,0.333333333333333,0.333333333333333,0.333333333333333,
0.333333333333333,0.333333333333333,0.333333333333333,0.333333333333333),(0.333333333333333,
0.333333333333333,0.333333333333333,0.333333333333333,0.333333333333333,0.333333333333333,
0.333333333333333,0.333333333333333,0.333333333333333,0.333333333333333,0.333333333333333,
0.333333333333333,0.333333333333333,0.333333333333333,0.333333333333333,0.333333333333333,
0.333333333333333,0.333333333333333,0.333333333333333,0.333333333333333,0.333333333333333,
0.333333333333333,0.333333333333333,0.333333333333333,0.333333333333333,0.333333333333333,
0.333333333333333,0.333333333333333,0.333333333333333,0.333333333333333,0.333333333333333,
0.333333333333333,0.333333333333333,0.333333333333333,0.333333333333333,0.333333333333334,
0.333333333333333,0.333333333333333,0.333333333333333,0.333333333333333,0.333333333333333,
0.333333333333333,0.333333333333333,0.333333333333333,0.333333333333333,0.333333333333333,
0.333333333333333,0.333333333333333,0.333333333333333,0.333333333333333,0.333333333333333,
0.333333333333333,0.333333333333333,0.333333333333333,0.333333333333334,0.333333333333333,
0.333333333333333,0.333333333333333,0.333333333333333,0.333333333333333,0.333333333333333,
0.333333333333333,0.333333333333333,0.333333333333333,0.333333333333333,0.333333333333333,
0.333333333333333,0.333333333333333,0.333333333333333,0.333333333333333,0.333333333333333,
0.333333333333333,0.333333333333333,0.333333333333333,0.333333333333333,0.333333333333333,
0.333333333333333,0.333333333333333,0.333333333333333,0.333333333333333,0.333333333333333,
0.333333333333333,0.333333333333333,0.333333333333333,0.333333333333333,0.333333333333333,
0.333333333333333,0.333333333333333,0.333333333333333,0.333333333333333,0.333333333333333,
0.333333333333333,0.333333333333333,0.333333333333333,0.333333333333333,0.333333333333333,
0.333333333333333,0.333333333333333,0.333333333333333),(1.,1.,1.,1.,1.,1.,1.,1.,1.,1.,
0.999999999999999,1.,1.,1.,1.,1.,1.,1.,1.,1.,1.,1.,1.,1.,1.,1.,1.,1.,1.,1.,1.,1.,1.,1.,1.,1.,1.,
1.,1.,1.,1.,1.,1.,1.,1.,1.,1.,1.,1.,1.,1.,1.,1.,1.,1.,1.,1.,1.,1.,1.,1.,1.,1.,1.,1.,1.,1.,1.,1.,
1.,1.,1.,1.,1.,1.,1.,1.,1.,1.,1.,1.,1.,1.,1.,1.,1.,1.,1.,1.,1.,1.,1.,1.,1.,1.,1.,1.,1.,1.),
(0.333333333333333,0.333333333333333,0.333333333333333,0.333333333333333,0.333333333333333,
0.333333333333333,0.333333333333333,0.333333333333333,0.333333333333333,0.333333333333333,
0.333333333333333,0.333333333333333,0.333333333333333,0.333333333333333,0.333333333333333,
0.333333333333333,0.333333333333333,0.333333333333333,0.333333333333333,0.333333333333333,
0.333333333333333,0.333333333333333,0.333333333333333,0.333333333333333,0.333333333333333,
0.333333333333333,0.333333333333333,0.333333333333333,0.333333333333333,0.333333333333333,
0.333333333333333,0.333333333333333,0.333333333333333,0.333333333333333,0.333333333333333,
0.333333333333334,0.333333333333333,0.333333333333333,0.333333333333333,0.333333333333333,
0.333333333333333,0.333333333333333,0.333333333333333,0.333333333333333,0.333333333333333,
0.333333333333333,0.333333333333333,0.333333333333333,0.333333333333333,0.333333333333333,
0.333333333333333,0.333333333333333,0.333333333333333,0.333333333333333,0.333333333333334,
0.333333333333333,0.333333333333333,0.333333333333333,0.333333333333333,0.333333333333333,
0.333333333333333,0.333333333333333,0.333333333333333,0.333333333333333,0.333333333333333,
0.333333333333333,0.333333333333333,0.333333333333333,0.333333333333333,0.333333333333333,
0.333333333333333,0.333333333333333,0.333333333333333,0.333333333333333,0.333333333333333,
0.333333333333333,0.333333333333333,0.333333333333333,0.333333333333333,0.333333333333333,
0.333333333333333,0.333333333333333,0.333333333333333,0.333333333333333,0.333333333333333,
0.333333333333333,0.333333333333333,0.333333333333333,0.333333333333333,0.333333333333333,
0.333333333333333,0.333333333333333,0.333333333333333,0.333333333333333,0.333333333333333,
0.333333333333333,0.333333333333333,0.333333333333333,0.333333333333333),(0.333333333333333,
0.333333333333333,0.333333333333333,0.333333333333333,0.333333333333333,0.333333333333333,
0.333333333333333,0.333333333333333,0.333333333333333,0.333333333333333,0.333333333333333,
0.333333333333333,0.333333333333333,0.333333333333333,0.333333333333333,0.333333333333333,
0.333333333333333,0.333333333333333,0.333333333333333,0.333333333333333,0.333333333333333,
0.333333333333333,0.333333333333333,0.333333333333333,0.333333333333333,0.333333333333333,
0.333333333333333,0.333333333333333,0.333333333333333,0.333333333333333,0.333333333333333,
0.333333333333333,0.333333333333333,0.333333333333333,0.333333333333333,0.333333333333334,
0.333333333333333,0.333333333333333,0.333333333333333,0.333333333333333,0.333333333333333,
0.333333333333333,0.333333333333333,0.333333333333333,0.333333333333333,0.333333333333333,
0.333333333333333,0.333333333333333,0.333333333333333,0.333333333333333,0.333333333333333,
0.333333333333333,0.333333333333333,0.333333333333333,0.333333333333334,0.333333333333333,
0.333333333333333,0.333333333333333,0.333333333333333,0.333333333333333,0.333333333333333,
0.333333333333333,0.333333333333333,0.333333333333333,0.333333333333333,0.333333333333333,
0.333333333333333,0.333333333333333,0.333333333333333,0.333333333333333,0.333333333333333,
0.333333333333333,0.333333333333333,0.333333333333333,0.333333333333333,0.333333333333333,
0.333333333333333,0.333333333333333,0.333333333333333,0.333333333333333,0.333333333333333,
0.333333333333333,0.333333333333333,0.333333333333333,0.333333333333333,0.333333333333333,
0.333333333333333,0.333333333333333,0.333333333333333,0.333333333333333,0.333333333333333,
0.333333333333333,0.333333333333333,0.333333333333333,0.333333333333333,0.333333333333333,
0.333333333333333,0.333333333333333,0.333333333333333),(1.,1.,1.,1.,1.,1.,1.,1.,1.,1.,
0.999999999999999,1.,1.,1.,1.,1.,1.,1.,1.,1.,1.,1.,1.,1.,1.,1.,1.,1.,1.,1.,1.,1.,1.,1.,1.,1.,1.,
1.,1.,1.,1.,1.,1.,1.,1.,1.,1.,1.,1.,1.,1.,1.,1.,1.,1.,1.,1.,1.,1.,1.,1.,1.,1.,1.,1.,1.,1.,1.,1.,
1.,1.,1.,1.,1.,1.,1.,1.,1.,1.,1.,1.,1.,1.,1.,1.,1.,1.,1.,1.,1.,1.,1.,1.,1.,1.,1.,1.,1.,1.))) REPRESENTATION_ITEM('') SURFACE());
#713=CARTESIAN_POINT('',(-9.70820393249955,7.05342302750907,16.9999999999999));
#714=DIRECTION('',(0.587793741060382,0.809010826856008,-8.30113570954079E-10));
#715=DIRECTION('',(-0.809010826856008,0.587793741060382,0.));
#716=AXIS2_PLACEMENT_3D('',#713,#714,#715);
#717=CIRCLE('',#716,1.5);
#718=CARTESIAN_POINT('',(-10.9217201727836,7.93511363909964,16.9999999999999));
#719=VERTEX_POINT('',#718);
#720=EDGE_CURVE('E36',#719,#719,#717,.T.);
#721=CARTESIAN_POINT('',(12.,0.,0.));
#722=DIRECTION('',(0.,1.,0.));
#723=DIRECTION('',(0.,0.,1.));
#724=AXIS2_PLACEMENT_3D('',#721,#722,#723);
#725=CIRCLE('',#724,1.5);
#726=CARTESIAN_POINT('',(10.5022041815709,0.,-0.0812876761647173));
#727=VERTEX_POINT('',#726);
#728=CARTESIAN_POINT('',(13.4977958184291,0.,-0.0812876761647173));
#729=VERTEX_POINT('',#728);
#730=EDGE_CURVE('E62',#727,#729,#725,.T.);
#731=CARTESIAN_POINT('',(13.4977958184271,3.28090756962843E-11,-0.0812876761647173));
#732=CARTESIAN_POINT('',(13.4893269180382,0.123580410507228,-0.0812876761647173));
#733=CARTESIAN_POINT('',(13.4808056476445,0.247159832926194,-0.0812876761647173));
#734=CARTESIAN_POINT('',(13.4631136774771,0.494522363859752,-0.0812876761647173));
#735=CARTESIAN_POINT('',(13.4539417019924,0.618305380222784,-0.0812876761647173));
#736=CARTESIAN_POINT('',(13.4344224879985,0.865921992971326,-0.0812876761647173));
#737=CARTESIAN_POINT('',(13.4240739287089,0.989755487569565,-0.0812876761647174));
#738=CARTESIAN_POINT('',(13.4016695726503,1.23731730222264,-0.0812876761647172));
#739=CARTESIAN_POINT('',(13.3896131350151,1.36104556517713,-0.081287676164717));
#740=CARTESIAN_POINT('',(13.3632434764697,1.608379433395,-0.0812876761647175));
#741=CARTESIAN_POINT('',(13.3489281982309,1.73198482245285,-0.0812876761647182));
#742=CARTESIAN_POINT('',(13.3175141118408,1.97877841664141,-0.0812876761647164));
#743=CARTESIAN_POINT('',(13.300416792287,2.10196680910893,-0.081287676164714));
#744=CARTESIAN_POINT('',(13.2629032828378,2.34777154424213,-0.0812876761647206));
#745=CARTESIAN_POINT('',(13.2424889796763,2.47038817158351,-0.0812876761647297));
#746=CARTESIAN_POINT('',(13.1978181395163,2.71489197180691,-0.0812876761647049));
#747=CARTESIAN_POINT('',(13.1735625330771,2.83677931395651,-0.0812876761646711));
#748=CARTESIAN_POINT('',(13.0995815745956,3.17653733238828,-0.0812876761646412));
#749=CARTESIAN_POINT('',(13.0449799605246,3.39336555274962,-0.0812876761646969));
#750=CARTESIAN_POINT('',(12.922700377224,3.8234907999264,-0.0812876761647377));
#751=CARTESIAN_POINT('',(12.8550098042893,4.03678420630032,-0.0812876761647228));
#752=CARTESIAN_POINT('',(12.7076221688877,4.45925710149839,-0.0812876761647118));
#753=CARTESIAN_POINT('',(12.627920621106,4.66843502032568,-0.0812876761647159));
#754=CARTESIAN_POINT('',(12.4575240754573,5.08217748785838,-0.0812876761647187));
#755=CARTESIAN_POINT('',(12.3668327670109,5.28674355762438,-0.0812876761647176));
#756=CARTESIAN_POINT('',(12.2232133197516,5.58992976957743,-0.0812876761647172));
#757=CARTESIAN_POINT('',(12.1740831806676,5.6903687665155,-0.0812876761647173));
#758=CARTESIAN_POINT('',(12.0733841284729,5.89001677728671,-0.0812876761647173));
#759=CARTESIAN_POINT('',(12.021815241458,5.98922580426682,-0.0812876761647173));
#760=CARTESIAN_POINT('',(11.8634672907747,6.28488771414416,-0.0812876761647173));
#761=CARTESIAN_POINT('',(11.7530376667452,6.47939499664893,-0.0812876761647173));
#762=CARTESIAN_POINT('',(11.4600238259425,6.96654441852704,-0.0812876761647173));
#763=CARTESIAN_POINT('',(11.2707803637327,7.25521675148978,-0.0812876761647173));
#764=CARTESIAN_POINT('',(10.8698206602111,7.81648109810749,-0.0812876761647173));
#765=CARTESIAN_POINT('',(10.6581060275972,8.08907426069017,-0.0812876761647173));
#766=CARTESIAN_POINT('',(10.2129809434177,8.61596717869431,-0.0812876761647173));
#767=CARTESIAN_POINT('',(9.97956946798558,8.87026606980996,-0.0812876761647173));
#768=CARTESIAN_POINT('',(9.49287347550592,9.35912294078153,-0.0812876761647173));
#769=CARTESIAN_POINT('',(9.23958623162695,9.59367820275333,-0.0812876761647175));
#770=CARTESIAN_POINT('',(8.70288232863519,10.0516321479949,-0.0812876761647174));
#771=CARTESIAN_POINT('',(8.41862001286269,10.2740415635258,-0.0812876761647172));
#772=CARTESIAN_POINT('',(7.83210933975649,10.6937002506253,-0.0812876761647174));
#773=CARTESIAN_POINT('',(7.52986113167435,10.8909497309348,-0.0812876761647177));
#774=CARTESIAN_POINT('',(6.90913588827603,11.2587483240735,-0.0812876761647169));
#775=CARTESIAN_POINT('',(6.59064618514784,11.4292761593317,-0.0812876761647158));
#776=CARTESIAN_POINT('',(6.1026826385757,11.6635272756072,-0.0812876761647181));
#777=CARTESIAN_POINT('',(5.93830733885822,11.7380268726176,-0.0812876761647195));
#778=CARTESIAN_POINT('',(5.60640859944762,11.8796466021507,-0.0812876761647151));
#779=CARTESIAN_POINT('',(5.43888517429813,11.9467667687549,-0.0812876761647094));
#780=CARTESIAN_POINT('',(4.94094502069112,12.133509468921,-0.0812876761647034));
#781=CARTESIAN_POINT('',(4.60652504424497,12.2426480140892,-0.0812876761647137));
#782=CARTESIAN_POINT('',(3.9293588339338,12.4311562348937,-0.0812876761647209));
#783=CARTESIAN_POINT('',(3.58661108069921,12.5105204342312,-0.0812876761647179));
#784=CARTESIAN_POINT('',(2.89595873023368,12.6378249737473,-0.0812876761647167));
#785=CARTESIAN_POINT('',(2.54806520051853,12.6858248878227,-0.0812876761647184));
#786=CARTESIAN_POINT('',(1.84951790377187,12.7491005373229,-0.0812876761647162));
#787=CARTESIAN_POINT('',(1.49886612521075,12.7643980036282,-0.0812876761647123));
#788=CARTESIAN_POINT('',(0.827054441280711,12.7604865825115,-0.0812876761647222));
#789=CARTESIAN_POINT('',(0.505887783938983,12.7440643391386,-0.0812876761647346));
#790=CARTESIAN_POINT('',(0.0267932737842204,12.6956114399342,-0.0812876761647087));
#791=CARTESIAN_POINT('',(-0.13239051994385,12.6755051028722,-0.0812876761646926));
#792=CARTESIAN_POINT('',(-0.449447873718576,12.6268530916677,-0.081287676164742));
#793=CARTESIAN_POINT('',(-0.607321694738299,12.5983091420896,-0.0812876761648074));
#794=CARTESIAN_POINT('',(-0.920768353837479,12.5320889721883,-0.0812876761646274));
#795=CARTESIAN_POINT('',(-1.07634598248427,12.4944359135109,-0.0812876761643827));
#796=CARTESIAN_POINT('',(-1.30746047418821,12.4299644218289,-0.0812876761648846));
#797=CARTESIAN_POINT('',(-1.38412052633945,12.4071429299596,-0.0812876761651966));
#798=CARTESIAN_POINT('',(-1.53647637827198,12.3584968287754,-0.081287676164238));
#799=CARTESIAN_POINT('',(-1.61217235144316,12.3326727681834,-0.0812876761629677));
#800=CARTESIAN_POINT('',(-1.75215437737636,12.2812211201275,-0.0812876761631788));
#801=CARTESIAN_POINT('',(-1.81660236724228,12.2560367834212,-0.0812876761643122));
#802=CARTESIAN_POINT('',(-1.94407150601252,12.2024912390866,-0.0812876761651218));
#803=CARTESIAN_POINT('',(-2.00709451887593,12.1741345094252,-0.0812876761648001));
#804=CARTESIAN_POINT('',(-2.12295943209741,12.1171860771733,-0.0812876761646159));
#805=CARTESIAN_POINT('',(-2.17605044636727,12.0891154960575,-0.0812876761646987));
#806=CARTESIAN_POINT('',(-2.25380664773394,12.0433875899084,-0.0812876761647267));
#807=CARTESIAN_POINT('',(-2.27949753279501,12.0274799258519,-0.0812876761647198));
#808=CARTESIAN_POINT('',(-2.32983404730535,11.9941142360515,-0.0812876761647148));
#809=CARTESIAN_POINT('',(-2.35448091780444,11.9766581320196,-0.0812876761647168));
#810=CARTESIAN_POINT('',(-2.39035128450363,11.9486885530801,-0.0812876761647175));
#811=CARTESIAN_POINT('',(-2.40220797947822,11.9389895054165,-0.0812876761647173));
#812=CARTESIAN_POINT('',(-2.42530438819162,11.9188872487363,-0.0812876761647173));
#813=CARTESIAN_POINT('',(-2.43654450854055,11.908484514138,-0.0812876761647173));
#814=CARTESIAN_POINT('',(-2.45801599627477,11.8868961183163,-0.0812876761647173));
#815=CARTESIAN_POINT('',(-2.46825678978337,11.8757199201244,-0.0812876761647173));
#816=CARTESIAN_POINT('',(-2.487339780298,11.852244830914,-0.0812876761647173));
#817=CARTESIAN_POINT('',(-2.49618718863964,11.8399504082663,-0.0812876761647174));
#818=CARTESIAN_POINT('',(-2.50780561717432,11.8201471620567,-0.0812876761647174));
#819=CARTESIAN_POINT('',(-2.51145883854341,11.813162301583,-0.0812876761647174));
#820=CARTESIAN_POINT('',(-2.51784323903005,11.7987723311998,-0.0812876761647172));
#821=CARTESIAN_POINT('',(-2.52057496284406,11.7913674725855,-0.0812876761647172));
#822=CARTESIAN_POINT('',(-2.52437151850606,11.777627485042,-0.0812876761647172));
#823=CARTESIAN_POINT('',(-2.52565358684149,11.771354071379,-0.0812876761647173));
#824=CARTESIAN_POINT('',(-2.52716847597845,11.7586853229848,-0.0812876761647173));
#825=CARTESIAN_POINT('',(-2.52740355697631,11.7522902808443,-0.0812876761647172));
#826=CARTESIAN_POINT('',(-2.52667210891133,11.739507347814,-0.0812876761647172));
#827=CARTESIAN_POINT('',(-2.52569523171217,11.7331199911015,-0.0812876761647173));
#828=CARTESIAN_POINT('',(-2.5225216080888,11.7206561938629,-0.0812876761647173));
#829=CARTESIAN_POINT('',(-2.52032440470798,11.7145798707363,-0.0812876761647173));
#830=CARTESIAN_POINT('',(-2.51464478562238,11.7024152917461,-0.0812876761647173));
#831=CARTESIAN_POINT('',(-2.5110668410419,11.696372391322,-0.0812876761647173));
#832=CARTESIAN_POINT('',(-2.50297656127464,11.6849359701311,-0.0812876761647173));
#833=CARTESIAN_POINT('',(-2.49846094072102,11.6795448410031,-0.0812876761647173));
#834=CARTESIAN_POINT('',(-2.48560116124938,11.6660452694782,-0.0812876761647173));
#835=CARTESIAN_POINT('',(-2.47669260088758,11.6584823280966,-0.0812876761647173));
#836=CARTESIAN_POINT('',(-2.45791519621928,11.6446812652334,-0.0812876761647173));
#837=CARTESIAN_POINT('',(-2.44804363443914,11.6384470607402,-0.0812876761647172));
#838=CARTESIAN_POINT('',(-2.42208809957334,11.6237455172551,-0.0812876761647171));
#839=CARTESIAN_POINT('',(-2.40561489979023,11.6159767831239,-0.0812876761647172));
#840=CARTESIAN_POINT('',(-2.37207090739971,11.6019776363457,-0.0812876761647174));
#841=CARTESIAN_POINT('',(-2.35500029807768,11.5957467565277,-0.0812876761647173));
#842=CARTESIAN_POINT('',(-2.32039411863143,11.5843007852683,-0.0812876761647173));
#843=CARTESIAN_POINT('',(-2.30285613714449,11.5790930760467,-0.0812876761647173));
#844=CARTESIAN_POINT('',(-2.26758066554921,11.5694537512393,-0.0812876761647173));
#845=CARTESIAN_POINT('',(-2.24984325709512,11.5650218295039,-0.0812876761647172));
#846=CARTESIAN_POINT('',(-2.20468963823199,11.5545125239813,-0.0812876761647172));
#847=CARTESIAN_POINT('',(-2.17718298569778,11.5488269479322,-0.0812876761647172));
#848=CARTESIAN_POINT('',(-2.12199333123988,11.5383768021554,-0.0812876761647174));
#849=CARTESIAN_POINT('',(-2.09431028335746,11.5336124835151,-0.0812876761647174));
#850=CARTESIAN_POINT('',(-2.01103389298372,11.5202751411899,-0.081287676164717));
#851=CARTESIAN_POINT('',(-1.95528701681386,11.5126730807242,-0.081287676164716));
#852=CARTESIAN_POINT('',(-1.84359273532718,11.4988361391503,-0.0812876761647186));
#853=CARTESIAN_POINT('',(-1.78764520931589,11.4926023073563,-0.0812876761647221));
#854=CARTESIAN_POINT('',(-1.67577229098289,11.4809093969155,-0.0812876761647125));
#855=CARTESIAN_POINT('',(-1.61984704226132,11.4754489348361,-0.0812876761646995));
#856=CARTESIAN_POINT('',(-1.50801637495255,11.4649137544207,-0.081287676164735));
#857=CARTESIAN_POINT('',(-1.45211099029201,11.4598386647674,-0.0812876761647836));
#858=CARTESIAN_POINT('',(-1.34030287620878,11.4498240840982,-0.0812876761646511));
#859=CARTESIAN_POINT('',(-1.28440014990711,11.4448845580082,-0.0812876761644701));
#860=CARTESIAN_POINT('',(-1.14439556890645,11.4324603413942,-0.081287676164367));
#861=CARTESIAN_POINT('',(-1.0602959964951,11.4249488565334,-0.0812876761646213));
#862=CARTESIAN_POINT('',(-0.892143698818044,11.4094267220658,-0.0812876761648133));
#863=CARTESIAN_POINT('',(-0.808090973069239,11.4014160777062,-0.081287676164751));
#864=CARTESIAN_POINT('',(-0.556051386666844,11.3762154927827,-0.08128767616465));
#865=CARTESIAN_POINT('',(-0.388177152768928,11.35785641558,-0.0812876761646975));
#866=CARTESIAN_POINT('',(-0.052955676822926,11.3166415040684,-0.0812876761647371));
#867=CARTESIAN_POINT('',(0.114391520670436,11.2937852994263,-0.0812876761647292));
#868=CARTESIAN_POINT('',(0.448283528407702,11.2428213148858,-0.0812876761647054));
#869=CARTESIAN_POINT('',(0.614828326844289,11.2147134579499,-0.0812876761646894));
#870=CARTESIAN_POINT('',(1.11269289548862,11.1218831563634,-0.081287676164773));
#871=CARTESIAN_POINT('',(1.44248241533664,11.0486260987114,-0.0812876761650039));
#872=CARTESIAN_POINT('',(2.09572760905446,10.8774215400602,-0.0812876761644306));
#873=CARTESIAN_POINT('',(2.41918117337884,10.7794659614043,-0.081287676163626));
#874=CARTESIAN_POINT('',(3.06062837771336,10.5568465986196,-0.0812876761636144));
#875=CARTESIAN_POINT('',(3.37852856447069,10.4319122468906,-0.0812876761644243));
#876=CARTESIAN_POINT('',(4.00274096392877,10.1559130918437,-0.0812876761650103));
#877=CARTESIAN_POINT('',(4.30905514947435,10.0048527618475,-0.0812876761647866));
#878=CARTESIAN_POINT('',(4.90781560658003,9.67658446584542,-0.0812876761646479));
#879=CARTESIAN_POINT('',(5.20024558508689,9.49934673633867,-0.0812876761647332));
#880=CARTESIAN_POINT('',(5.7685585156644,9.11998707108,-0.0812876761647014));
#881=CARTESIAN_POINT('',(6.04443914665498,8.91786165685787,-0.0812876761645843));
#882=CARTESIAN_POINT('',(6.57401123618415,8.49267283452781,-0.0812876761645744));
#883=CARTESIAN_POINT('',(6.82793387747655,8.26989753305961,-0.081287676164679));
#884=CARTESIAN_POINT('',(7.31500910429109,7.80273799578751,-0.0812876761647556));
#885=CARTESIAN_POINT('',(7.54816468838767,7.55835688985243,-0.0812876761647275));
#886=CARTESIAN_POINT('',(7.99140195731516,7.04969365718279,-0.0812876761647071));
#887=CARTESIAN_POINT('',(8.20149509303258,6.78542151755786,-0.0812876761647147));
#888=CARTESIAN_POINT('',(8.59651351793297,6.23864879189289,-0.0812876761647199));
#889=CARTESIAN_POINT('',(8.7814383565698,5.95614787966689,-0.0812876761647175));
#890=CARTESIAN_POINT('',(9.06125485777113,5.48410894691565,-0.0812876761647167));
#891=CARTESIAN_POINT('',(9.16401182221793,5.29917196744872,-0.0812876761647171));
#892=CARTESIAN_POINT('',(9.35923609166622,4.92391357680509,-0.0812876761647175));
#893=CARTESIAN_POINT('',(9.4517026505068,4.73359177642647,-0.0812876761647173));
#894=CARTESIAN_POINT('',(9.62624821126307,4.34816286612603,-0.0812876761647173));
#895=CARTESIAN_POINT('',(9.70832343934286,4.15305404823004,-0.0812876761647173));
#896=CARTESIAN_POINT('',(9.86094869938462,3.75825295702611,-0.0812876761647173));
#897=CARTESIAN_POINT('',(9.93149451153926,3.55855903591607,-0.0812876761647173));
#898=CARTESIAN_POINT('',(10.0276420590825,3.25602446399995,-0.0812876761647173));
#899=CARTESIAN_POINT('',(10.058074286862,3.15470111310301,-0.0812876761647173));
#900=CARTESIAN_POINT('',(10.1155481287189,2.95109272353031,-0.0812876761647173));
#901=CARTESIAN_POINT('',(10.1425897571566,2.84880768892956,-0.0812876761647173));
#902=CARTESIAN_POINT('',(10.1930948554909,2.64346384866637,-0.0812876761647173));
#903=CARTESIAN_POINT('',(10.2165618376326,2.54040590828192,-0.0812876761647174));
#904=CARTESIAN_POINT('',(10.2596945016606,2.33350099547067,-0.0812876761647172));
#905=CARTESIAN_POINT('',(10.279360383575,2.22965406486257,-0.0812876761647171));
#906=CARTESIAN_POINT('',(10.3072986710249,2.06696850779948,-0.0812876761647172));
#907=CARTESIAN_POINT('',(10.3167891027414,2.00833499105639,-0.0812876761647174));
#908=CARTESIAN_POINT('',(10.3347613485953,1.89091491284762,-0.0812876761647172));
#909=CARTESIAN_POINT('',(10.3432431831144,1.83212835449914,-0.081287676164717));
#910=CARTESIAN_POINT('',(10.3673150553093,1.65554156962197,-0.0812876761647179));
#911=CARTESIAN_POINT('',(10.3815250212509,1.53755250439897,-0.0812876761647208));
#912=CARTESIAN_POINT('',(10.4070460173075,1.30121109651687,-0.0812876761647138));
#913=CARTESIAN_POINT('',(10.4183556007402,1.18285860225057,-0.0812876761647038));
#914=CARTESIAN_POINT('',(10.4388226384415,0.94619443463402,-0.0812876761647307));
#915=CARTESIAN_POINT('',(10.447984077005,0.827883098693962,-0.0812876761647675));
#916=CARTESIAN_POINT('',(10.4649445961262,0.591235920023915,-0.0812876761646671));
#917=CARTESIAN_POINT('',(10.4727444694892,0.472900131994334,-0.0812876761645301));
#918=CARTESIAN_POINT('',(10.4877366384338,0.236373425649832,-0.0812876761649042));
#919=CARTESIAN_POINT('',(10.4949298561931,0.118182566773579,-0.0812876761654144));
#920=CARTESIAN_POINT('',(10.502204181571,0.,-0.0812876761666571));
#921=B_SPLINE_CURVE_WITH_KNOTS('',3,(#731,#732,#733,#734,#735,#736,#737,#738,#739,#740,#741,
#742,#743,#744,#745,#746,#747,#748,#749,#750,#751,#752,#753,#754,#755,#756,#757,#758,#759,#760,
#761,#762,#763,#764,#765,#766,#767,#768,#769,#770,#771,#772,#773,#774,#775,#776,#777,#778,#779,
#780,#781,#782,#783,#784,#785,#786,#787,#788,#789,#790,#791,#792,#793,#794,#795,#796,#797,#798,
#799,#800,#801,#802,#803,#804,#805,#806,#807,#808,#809,#810,#811,#812,#813,#814,#815,#816,#817,
#818,#819,#820,#821,#822,#823,#824,#825,#826,#827,#828,#829,#830,#831,#832,#833,#834,#835,#836,
#837,#838,#839,#840,#841,#842,#843,#844,#845,#846,#847,#848,#849,#850,#851,#852,#853,#854,#855,
#856,#857,#858,#859,#860,#861,#862,#863,#864,#865,#866,#867,#868,#869,#870,#871,#872,#873,#874,
#875,#876,#877,#878,#879,#880,#881,#882,#883,#884,#885,#886,#887,#888,#889,#890,#891,#892,#893,
#894,#895,#896,#897,#898,#899,#900,#901,#902,#903,#904,#905,#906,#907,#908,#909,#910,#911,#912,
#913,#914,#915,#916,#917,#918,#919,#920),.UNSPECIFIED.,.F.,.F.,(4,2,2,2,2,2,2,2,2,2,2,2,2,2,2,2,
2,2,2,2,2,2,2,2,2,2,2,2,2,2,2,2,2,2,2,2,2,2,2,2,2,2,2,2,2,2,2,2,2,2,2,2,2,2,2,2,2,2,2,2,2,2,2,2,
2,2,2,2,2,2,2,2,2,2,2,2,2,2,2,2,2,2,2,2,2,2,2,2,2,2,2,2,2,2,4),(0.,0.37161502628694,
0.743979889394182,1.11676695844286,1.48969428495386,1.86296325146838,2.23603314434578,
2.60889156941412,2.98165980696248,3.65196822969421,4.32292535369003,4.99413366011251,
5.66511725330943,6.00052340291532,6.33592596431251,7.00666619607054,8.04106460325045,
9.07538900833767,10.1097622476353,11.1442776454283,12.2257378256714,13.3071890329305,
14.3894970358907,14.9307529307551,15.4720063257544,16.5258974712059,17.5799823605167,
18.6320592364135,19.6834367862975,20.646628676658,21.1277871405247,21.6088473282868,
22.0886969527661,22.3286040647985,22.5684674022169,22.7759799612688,22.9832032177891,
23.1631800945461,23.2537974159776,23.3443038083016,23.3902394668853,23.436144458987,
23.4815630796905,23.5268075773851,23.550409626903,23.5739977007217,23.593136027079,
23.6122330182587,23.6314941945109,23.6507625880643,23.671714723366,23.6927415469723,
23.7276007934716,23.7625614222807,23.8170566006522,23.8715352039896,23.9263934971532,
23.9812300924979,24.0654679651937,24.149728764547,24.3184759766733,24.4873521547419,
24.6559223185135,24.8243279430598,24.992689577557,25.2459918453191,25.4992914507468,
26.0058727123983,26.5124957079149,27.0191261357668,28.03166484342,29.0445351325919,
30.0680788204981,31.0914474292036,32.115988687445,33.1406733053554,34.152754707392,
35.1646897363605,36.176120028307,37.1875684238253,37.8219860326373,38.4564496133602,
39.0911429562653,39.7260680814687,40.0434044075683,40.3607393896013,40.6777605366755,
40.9947649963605,41.1729467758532,41.3511249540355,41.707597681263,42.0642478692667,
42.4202312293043,42.7760066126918,43.1312310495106),.UNSPECIFIED.);
#922=EDGE_CURVE('E47',#729,#727,#921,.T.);
#923=ORIENTED_EDGE('',*,*,#720,.T.);
#924=EDGE_LOOP('',(#923));
#925=FACE_BOUND('',#924,.T.);
#926=ORIENTED_EDGE('',*,*,#730,.T.);
#927=ORIENTED_EDGE('',*,*,#922,.T.);
#928=EDGE_LOOP('',(#926,#927));
#929=FACE_BOUND('',#928,.T.);
#930=ADVANCED_FACE('F28',(#925,#929),#712,.T.);
#931=CARTESIAN_POINT('',(0.,0.,0.));
#932=DIRECTION('',(0.,0.,1.));
#933=DIRECTION('',(1.,0.,0.));
#934=AXIS2_PLACEMENT_3D('',#931,#932,#933);
#935=TOROIDAL_SURFACE('',#934,12.,1.5);
#936=CARTESIAN_POINT('',(0.,0.,-0.0812876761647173));
#937=DIRECTION('',(0.,0.,-1.));
#938=DIRECTION('',(-1.,0.,0.));
#939=AXIS2_PLACEMENT_3D('',#936,#937,#938);
#940=CIRCLE('',#939,13.4977958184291);
#941=CARTESIAN_POINT('',(-6.74889790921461,-11.689434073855,-0.0812876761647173));
#942=VERTEX_POINT('',#941);
#943=EDGE_CURVE('E43',#729,#942,#940,.T.);
#944=ORIENTED_EDGE('',*,*,#943,.F.);
#945=ORIENTED_EDGE('',*,*,#730,.F.);
#946=CARTESIAN_POINT('',(0.,0.,-0.0812876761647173));
#947=DIRECTION('',(0.,0.,1.));
#948=DIRECTION('',(1.,0.,0.));
#949=AXIS2_PLACEMENT_3D('',#946,#947,#948);
#950=CIRCLE('',#949,10.5022041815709);
#951=CARTESIAN_POINT('',(-5.25110209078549,-9.09517561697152,-0.0812876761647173));
#952=VERTEX_POINT('',#951);
#953=EDGE_CURVE('E53',#952,#727,#950,.T.);
#954=ORIENTED_EDGE('',*,*,#953,.F.);
#955=CARTESIAN_POINT('',(-6.00000000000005,-10.3923048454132,0.));
#956=DIRECTION('',(-0.866025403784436,0.500000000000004,0.));
#957=DIRECTION('',(0.,0.,-1.));
#958=AXIS2_PLACEMENT_3D('',#955,#956,#957);
#959=CIRCLE('',#958,1.5);
#960=EDGE_CURVE('E60',#942,#952,#959,.T.);
#961=ORIENTED_EDGE('',*,*,#960,.F.);
#962=EDGE_LOOP('',(#944,#945,#954,#961));
#963=FACE_BOUND('',#962,.T.);
#964=ADVANCED_FACE('F59',(#963),#935,.T.);
#965=CARTESIAN_POINT('',(-6.00000000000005,-10.3923048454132,0.));
#966=DIRECTION('',(-0.866025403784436,0.500000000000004,0.));
#967=DIRECTION('',(0.,0.,-1.));
#968=AXIS2_PLACEMENT_3D('',#965,#966,#967);
#969=PLANE('',#968);
#970=ORIENTED_EDGE('',*,*,#960,.T.);
#971=DIRECTION('',(-0.500000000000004,-0.866025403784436,0.));
#972=VECTOR('',#971,1.);
#973=CARTESIAN_POINT('',(-6.00000000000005,-10.3923048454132,-0.0812876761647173));
#974=LINE('',#973,#972);
#975=EDGE_CURVE('E11',#952,#942,#974,.T.);
#976=ORIENTED_EDGE('',*,*,#975,.T.);
#977=EDGE_LOOP('',(#970,#976));
#978=FACE_BOUND('',#977,.T.);
#979=ADVANCED_FACE('F64',(#978),#969,.T.);
#980=CARTESIAN_POINT('',(-9.70839594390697,7.05356253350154,15.5000000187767));
#981=DIRECTION('',(0.587793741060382,0.809010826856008,-8.30113538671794E-10));
#982=DIRECTION('',(-0.809010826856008,0.587793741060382,0.));
#983=AXIS2_PLACEMENT_3D('',#980,#981,#982);
#984=PLANE('',#983);
#985=ORIENTED_EDGE('',*,*,#720,.F.);
#986=EDGE_LOOP('',(#985));
#987=FACE_BOUND('',#986,.T.);
#988=ADVANCED_FACE('F30',(#987),#984,.F.);
#989=CARTESIAN_POINT('',(-74.3828446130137,12.4910886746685,-0.0812876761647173));
#990=DIRECTION('',(0.,0.,-1.));
#991=DIRECTION('',(-1.,0.,0.));
#992=AXIS2_PLACEMENT_3D('',#989,#990,#991);
#993=PLANE('',#992);
#994=ORIENTED_EDGE('',*,*,#922,.F.);
#995=ORIENTED_EDGE('',*,*,#943,.T.);
#996=ORIENTED_EDGE('',*,*,#975,.F.);
#997=ORIENTED_EDGE('',*,*,#953,.T.);
#998=EDGE_LOOP('',(#994,#995,#996,#997));
#999=FACE_BOUND('',#998,.T.);
#1000=ADVANCED_FACE('F52',(#999),#993,.T.);
#1001=CLOSED_SHELL('',(#930,#964,#979,#988,#1000));
#1002=MANIFOLD_SOLID_BREP('B2',#1001);
#1003=ADVANCED_BREP_SHAPE_REPRESENTATION('',(#18,#1002),#14);
#1004=SHAPE_DEFINITION_REPRESENTATION(#9,#1003);
ENDSEC;
END-ISO-10303-21;
